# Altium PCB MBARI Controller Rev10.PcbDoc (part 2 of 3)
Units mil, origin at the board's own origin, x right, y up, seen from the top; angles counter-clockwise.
Board outline 10420.2 x 10420.2 mil, 2 copper layers (Top Layer, Bottom Layer); 286 components, 204 nets, 1058 pads, 249 vias.
Unrouted connection lines stored in the file: 1.

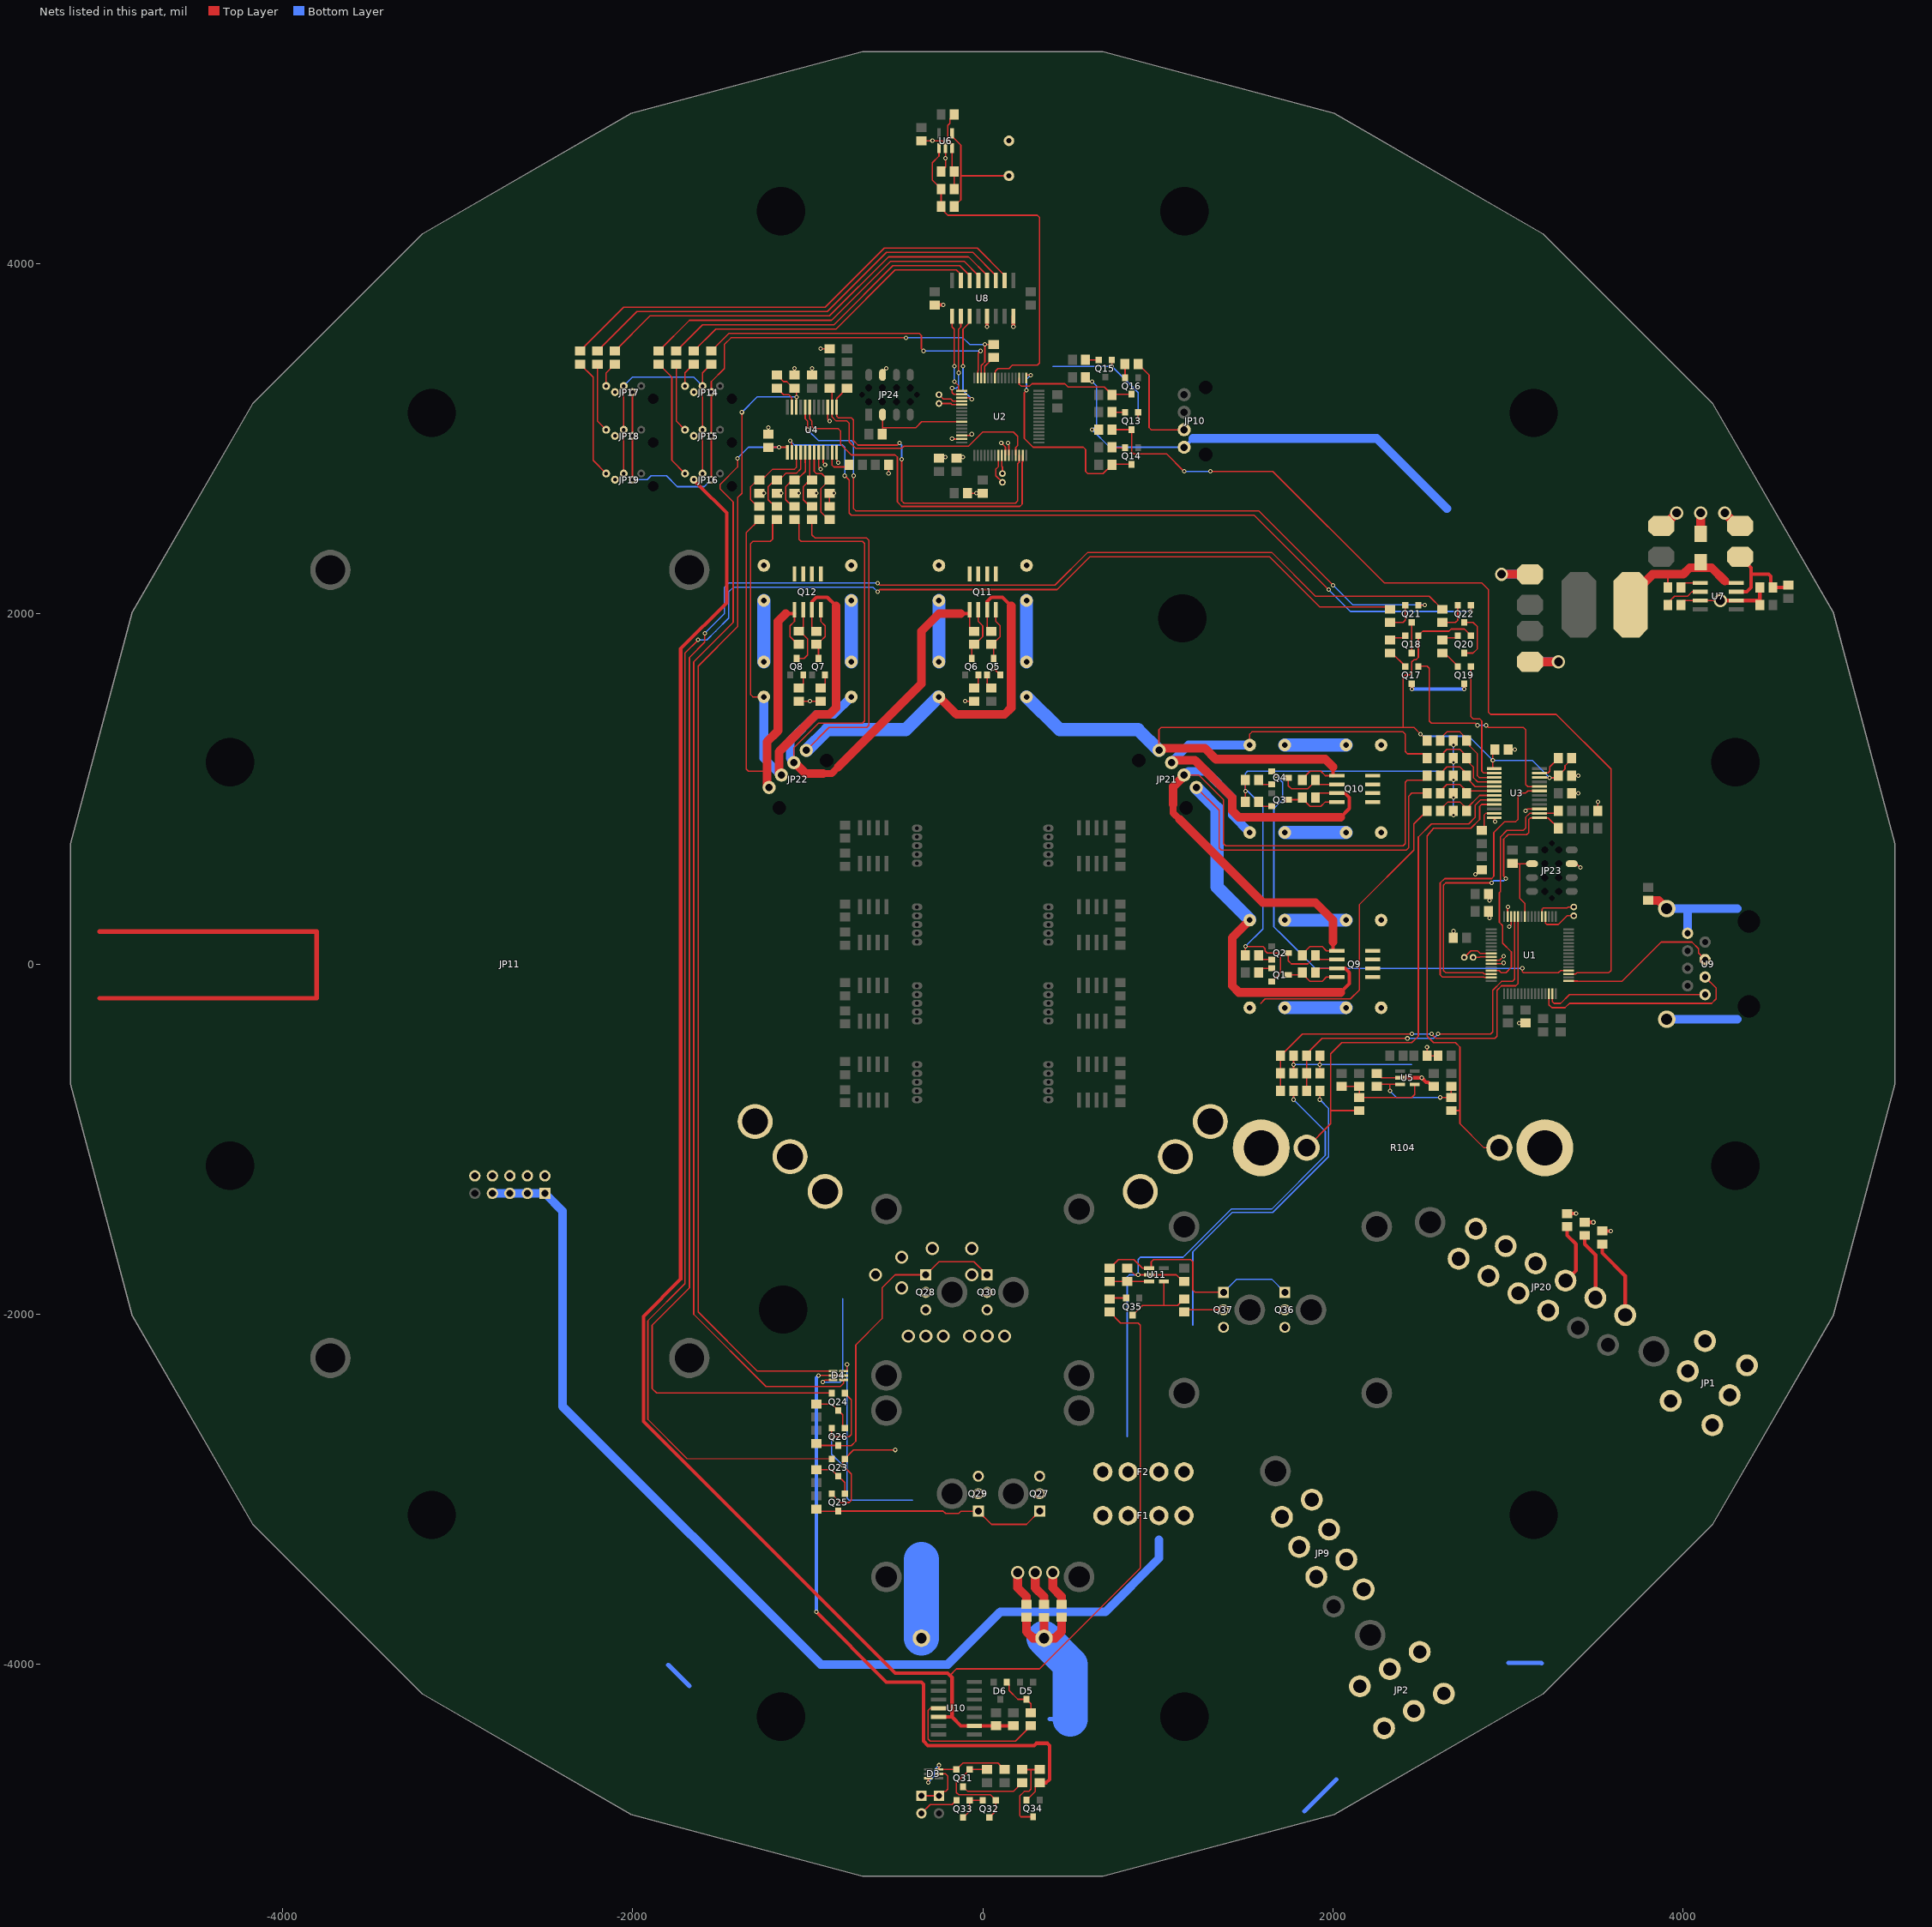
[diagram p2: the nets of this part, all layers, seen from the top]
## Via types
v1: diameter 25, hole 15, Top Layer to Bottom Layer, 204 vias
v2: diameter 40, hole 22, Top Layer to Bottom Layer, 24 vias
v3: diameter 75, hole 50, Top Layer to Bottom Layer, 21 vias

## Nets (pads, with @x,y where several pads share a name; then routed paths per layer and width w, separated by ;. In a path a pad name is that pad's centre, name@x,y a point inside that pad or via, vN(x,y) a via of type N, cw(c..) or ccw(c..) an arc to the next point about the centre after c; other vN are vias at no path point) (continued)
AGNDU: C2.1 C4.1 C6.2 C8.2 C12.2 C14.1 C16.1 C20.1 C21.2 C22.1 C23.2 C24.1 C30.1 C31.1 C32.1 C33.1 C34.1 C35.1 C39.1 C41.2 JP14.4 JP15.4 JP16.4 JP17.4 JP18.4 JP19.4 JP21.4 JP24.7 Q5.2 Q10.1 Q13.1 Q15.1 Q18.1 Q20.1 R12.1 R30.2 R56.1 R62.2 R71.1 R75.2 R76.1 R80.1 R84.1 R103.2 RH1.2 U2.10 U2.11 U2.62 U2.63 U3.1 U3.22 U4.8 U4.9 U4.12 U4.15 U6.2 U8.5 U8.8 U10.5 U10.9 | length 20293.5
  Top Layer w8: C30.1@-1275,2687.5 v1(-1250,2687.5) ; C24.1@-1225,3024.8 v1(-1225,3062.5) ; C31.1@-1175,2687.6 C31.1@-1150.1,2687.6 ; C32.1@-1075,2687.6 C32.1@-1050.1,2687.6 ; C22.1@-1075,3362.4 v1(-1075,3400) ; R84.1@-1050,1500.2 R80.1@-925,1500.2 ; C33.1@-975,2687.6 C33.1@-950.1,2687.6 ; C4.1@-975,3362.4 v1(-975,3400) ; U4.8@-936.61,2921.06 -936.61,2836.61 v1(-925,2825) ; v1(-925,3512.5) -924.9,3512.4 C8.2@-875,3512.4 ; U4.9@-911.02,2921.06 -911.02,2861.02 v1(-900,2850) ; U4.15@-885.43,3178.94 -885.43,3110.43 v1(-875,3100) ; R71.1@-875,2612.4 C34.1@-875,2687.6 v1(-850.1,2687.6) ; U4.12@-834.25,2921.06 -834.25,2871.75 v1(-825,2862.5) ; JP24.7@-571.85,3363.19 -571.85,3378.15 v1(-550,3400) ; v1(-537.5,2800) C20.1@-537.5,2850 ; C35.1@-350,4700 -231.25,4700 U6.2@-212.5,4681.25 ; R56.1@-237.5,4525 -212.5,4550 U6.2@-212.5,4657.68 ; C6.2@-231.25,2893.75 v1(-212.5,2893.75) ; v1@-225.2,3762.7 v1(-225,3762.5) ; -187.5,-4062.5 -150,-4025 325,-4025 900,-3450 900,-2062.5 887.5,-2050 787.5,-2050 725,-1987.5 R62.2@725,-1987.4 ; v1(-175,3000) -172.05,2997.05 U2.63@-120.47,2997.05 ; C2.1@-131.25,2893.75 v1(-112.5,2893.75) ; U2.62@-120.47,3016.73 -70.77,3016.73 v1(-62.5,3025) ; v1(-100,1500) R76.1@-50,1500 ; C12.2@-87.6,2687.5 v1@-37.5,2687.5 ; v1(-37.4,2687.6) C14.1@0,2687.6 ; v1(62.5,1687.5) 99.8,1650.2 Q5.2@99.8,1650 ; v1(106.25,2975) 129.53,2951.72 U2.10@129.53,2904.53 ; v1(143.75,2975) 149.21,2961.71 U2.11@149.21,2904.53 ; v1@737.4,3412.6 Q15.1@737.4,3449.21 ; v1@887.4,3112.6 Q13.1@887.4,3149.21 ; JP21.4@1001.01,1219.76 JP21.4@1007.63,1219.76 JP21.4@1007.63,1220.13 ; JP21.4@1006.25,1221.14 1006.25,1337.5 1018.75,1350 2462.6,1350 v1(2500,1312.5) R12.1@2537.6,1275 R12.1@2537.5,1275 ; R30.2@1825.2,1050 1825.2,1056.45 1868.75,1100 1931.25,1100 1956.25,1075 Q10.1@2022.64,1075 ; 2400,1350 2400,1637.5 2412.5,1650 2437.5,1650 2450,1662.5 2450,1725 2462.7,1737.7 2475,1737.7 2487.4,1750.1 2487.4,1874.9 2512.5,1900 2662.5,1900 2675,1912.5 2750,1912.5 Q20.1@2787.4,1875.1 ; Q20.1@2787.4,1873.43 Q20.1@2787.4,1887.6 ; U3.1@2921.06,1115.75 2921.06,1116.44 2912.5,1125 2912.5,1212.5 C23.2@2925,1225 ; U3.22@3178.94,1064.57 3222.93,1064.57 3225,1062.5 3275.2,1062.5 3325,1112.3 3325,1131.25 3362.5,1168.75 R103.2@3362.5,1175
  Top Layer w20: JP16.4@-1650,2765 -1625,2737.5 -1462.5,2575 -1462.5,2062.5 -1725,1800 -1725,-1800 -1937.5,-2012.5 -1937.5,-2612.5 -500,-4050 -200,-4050 -175,-4075 -175,-4300 ; C16.1@-275,3762.7 v1@-225.2,3762.7 ; U10.5@-252.36,-4300 -175,-4300 ; v1(25,3637.5) U8.5@25,3700 ; C41.2@174.8,-4350 C39.1@75,-4350 -125,-4350 -175,-4300 ; v1(175,3637.5) U8.8@175,3697.64 ; Q10.1@2000,1075 2000,1125
  Top Layer w50: JP21.4@1007.63,1219.76 1019.12,1231.25 1050,1231.25 1268.75,1231.25 1331.25,1168.75 1956.25,1168.75 2000,1125
  Bottom Layer w8: 400.76,3412.5 418.75,3412.5 v1@737.4,3412.6 ; v1(737.5,3412.5) 887.5,3262.5 v1(887.5,3112.5) ; v1(2500,1312.5) 2512.5,1300 2775,1300 v1(2912.5,1162.5) 3137.5,1162.5 v1(3237.5,1062.5)
  Bottom Layer w50: JP21.4@1005.24,1219.76 JP21.4@1007.63,1219.76
  Bottom Layer w75: R75.2@250,1525 440.23,1337.5 887.5,1337.5 JP21.4@1005.24,1219.76
  other v1: -987.5,1500.2 -1150,2687.5 -1050,2687.5 -950,2687.5 -212.5,4600 -287.5,4700
BAT+: D4.3 JP6.1 JP7.1 JP8.1 Q28.2 Q30.2 | length 642.1
  Top Layer w8: v1(-912.5,-2387.5) -900.59,-2375.59 D4.3@-855.51,-2375.59
  Bottom Layer w8: v1(-912.5,-2387.5) -812.5,-2387.5 -800,-2375 -800,-1912.5
  other v3: -462.5,-1850 -612.5,-1775 -62.5,-1775 -462.5,-1675 -287.5,-1625 -62.5,-1625
BAT-: JP3.1 JP4.1 JP5.1 R16.1 R20.2 R104.4 | length 1779.2
  Top Layer w8: 1587.5,-225 1612.5,-200 2100,-200 2150,-150 2150,162.5 2150,337.5 2462.5,650 2462.5,800 2537.5,875 R16.1@2537.6,875
CS0: JP14.5 R45.2 | length 148.5
  Top Layer w8: JP14.5@-1702.73,3300.73 JP14.5@-1700,3300 -1700,3375 R45.2@-1650,3425
CS1: JP15.5 R46.2 | length 395.7
  Top Layer w8: R46.2@-1750,3425 -1750,3100 JP15.5@-1700,3050
CS2: JP16.5 R47.2 | length 687.1
  Top Layer w8: R47.2@-1850,3425 -1775,3350 -1775,2875 JP16.5@-1700,2800
CS3: JP17.5 R48.2 | length 148.8
  Top Layer w8: JP17.5@-2152.74,3300.73 JP17.5@-2150,3300 ; JP17.5@-2150.22,3300.06 JP17.5@-2150,3300 ; R48.2@-2100,3425 -2150,3375 JP17.5@-2150,3300
CS4: JP18.5 R49.2 | length 397.6
  Top Layer w8: R49.2@-2200,3425 -2200,3100 JP18.5@-2150,3050 JP18.5@-2151.62,3049.06
CS5: JP19.5 R50.2 | length 687.1
  Top Layer w8: R50.2@-2300,3425 -2225,3350 -2225,2875 JP19.5@-2150,2800
CTS: U1.31 U9.8 | length 941.7
  Top Layer w8: U1.31@3252.95,-170.47 3252.95,-215.45 3262.5,-225 3300,-225 3350,-175 U9.8@4125,-175
F_RH: R54.2 R57.2 U2.42 U6.1 | length 2107.9
  Top Layer w8: U6.1@-249.9,4657.68 -249.9,4612.6 -287.5,4575 -287.5,4475.2 -237.5,4425.2 -237.5,4425 R54.2@-237.5,4325 ; R54.2@-237.4,4325 -237.4,4312.4 -200,4275 312.5,4275 325,4262.5 325,3431.25 312.5,3418.75 168.75,3418.75 150,3400 87.5,3400 72.25,3384.75 72.25,3378.5 70.47,3376.72 U2.42@70.47,3345.47
FUSE_EXT: C17.2 R58.1 R59.2 U1.61 | length 2072.8
  Top Layer w8: R58.1@1850,-725 R59.2@1850,-625 ; R59.2@1850.2,-624.8 1850.2,-512.5 1937.7,-425 v1(2425,-425) ; v1(2600,-400) 2675,-400 2700,-400 2900,-400 2912.5,-387.5 2912.5,-150 2962.5,-100 3025,-100 3037.5,-87.5 3037.5,168.75 3037.5,181.25 3037.5,218.75 3036.42,232.33 U1.61@3036.42,270.47
  Bottom Layer w8: v1(2425,-425) 2575,-425 v1(2600,-400)
FUSE_INT: C18.2 R60.1 R61.2 U1.60 | length 2284.4
  Top Layer w8: R60.1@1700.2,-725 C18.2@1700.2,-525 1825.2,-400 v1(2450,-400) ; v1(2562.5,-400) 2587.5,-425 2925,-425 2937.5,-412.5 2937.5,-150 2962.5,-125 3043.75,-125 3056.25,-112.5 3056.25,231.25 3056.1,231.4 U1.60@3056.1,270.47
  Bottom Layer w8: v1(2450,-400) v1(2562.5,-400)
NetC10_1: C10.1 R1.1@2150,-762.6 R3.2 U5.4 | length 545
  Top Layer w8: C10.1@2050,-699.9 R3.2@2150,-699.9 R1.1@2150,-762.6 2449.9,-762.6 2467.32,-745.18 U5.4@2467.32,-687.4
NetC22_2: C22.2 D4.1 R66.2 U4.22 | length 6743.1
  Top Layer w8: v1(-1375,3150) -1375,2687.5 -1400,2662.5 -1400,1925 -1625,1700 -1625,-1987.5 -1287.5,-2325 D4.1@-855.51,-2324.41 ; R66.2@-1175,3362.5 -1137.5,3325 -1118.75,3325 -1081.35,3287.6 C22.2@-1075,3287.6 -1064.57,3277.17 U4.22@-1064.57,3178.94
  Bottom Layer w8: v1(-1375,3150) -1287.5,3237.5 v1(-1062.5,3237.5)
NetC24_2: C24.2 D4.4 U4.1 | length 6505.6
  Top Layer w8: v1(-1400,2887.5) -1400,2837.5 -1500,2737.5 -1500,2712.5 -1425,2637.5 -1425,1950 -1650,1725 -1650,-2000 -1237.5,-2412.5 -812.5,-2412.5 -794.49,-2394.49 D4.4@-794.49,-2375.59 ; C24.2@-1225,2950 -1119,2950 -1115.75,2946.75 U4.1@-1115.75,2921.06
  Bottom Layer w8: v1(-1400,2887.5) -1337.5,2950 v1(-1162.5,2950)
NetC25_2: C25.2 R12.2 U3.3 | length 507.4
  Top Layer w8: R12.2@2612.4,1275 2612.4,1287.4 2650,1325 2725,1325 2762.4,1287.6 C25.2@2762.4,1275 2781.25,1256.25 2781.25,1243.75 2825,1200 2825,1075 2835.43,1064.57 U3.3@2896.06,1064.57
NetC26_2: C26.2 R13.2 U3.4 | length 399.2
  Top Layer w8: R13.2@2612.4,1187.4 2650,1225 2725,1225 2762.4,1187.6 C26.2@2762.4,1175 ; C26.2@2781.25,1156.15 2781.25,1143.75 2802.95,1122.05 2802.95,1062.5 2826.48,1038.98 U3.4@2896.06,1038.98
NetC27_2: C27.2 R14.2 U3.5 | length 360.5
  Top Layer w8: R14.2@2612.4,1087.4 2650,1125 2725,1125 2762.4,1087.6 C27.2@2762.4,1075 2781.25,1056.15 2781.25,1043.75 2812.5,1012.5 2825,1012.5 U3.5@2896.06,1013.39
NetC28_2: C28.2 R15.2 U3.6 | length 357.4
  Top Layer w8: R15.2@2612.4,975 2612.4,987.4 2650,1025 2725,1025 2762.4,987.6 C28.2@2762.4,975 2765.69,975 2778.19,987.5 2818.75,987.5 U3.6@2908.56,987.79
NetC29_2: C29.2 R16.2 U3.7 | length 390.9
  Top Layer w8: R16.2@2612.4,875 2618.65,887.4 2656.25,925 2725,925 2762.4,887.6 C29.2@2762.4,875 ; C29.2@2762.4,887.4 2837.2,962.2 U3.7@2921.06,962.2
NetC30_2: C30.2 R67.2 U4.3 | length 507.3
  Top Layer w8: R67.2@-1275,2612.4 -1287.4,2612.4 -1325,2650 -1325,2725 -1287.6,2762.4 C30.2@-1275,2762.4 C30.2@-1256.25,2781.15 ; C30.2@-1256.25,2781.25 -1243.75,2781.25 -1200,2825 -1075,2825 -1064.57,2835.43 U4.3@-1064.57,2896.06
NetC31_2: C31.2 R68.2 U4.4 | length 386.6
  Top Layer w8: C31.2@-1187.6,2762.4 -1225,2725 -1225,2650 R68.2@-1187.4,2612.4 ; C31.2@-1156.15,2781.25 -1143.75,2781.25 -1122.05,2802.95 -1062.5,2802.95 -1038.98,2826.48 U4.4@-1038.98,2896.06
NetC32_2: C32.2 R69.2 U4.5 | length 321.2
  Top Layer w8: C32.2@-1087.6,2762.4 -1125,2725 -1125,2650 R69.2@-1087.4,2612.4 ; C32.2@-1056.15,2781.25 -1043.75,2781.25 -1012.5,2812.5 -1012.5,2825 U4.5@-1013.39,2896.06
NetC33_2: C33.2 R70.2 U4.6 | length 311.4
  Top Layer w8: U4.6@-987.79,2908.56 -987.5,2818.75 C33.2@-987.5,2778.19 ; C33.2@-987.6,2762.4 -1025,2725 -1025,2650 R70.2@-987.4,2612.4
NetC34_2: C34.2 R71.2 U4.7 | length 486.8
  Top Layer w8: U4.7@-962.21,2921.06 -962.5,2812.5 -950,2800 -918.75,2800 -881.15,2762.4 C34.2@-875,2762.4 -925,2712.4 -925,2581.25 -881.35,2537.6 R71.2@-875,2537.6
NetC40_1: C40.1 D5.3 D6.1 | length 262
  Top Layer w8: D6.1@138.29,-4100.79 D6.1@137.4,-4100.79 150,-4113.38 150,-4148.42 200.79,-4199.21 D5.3@250,-4199.21 ; D5.3@249.21,-4200 D5.3@250,-4199.21 ; C40.1@275,-4275 275,-4224.21 D5.3@250,-4199.21
NetC40_2: C40.2 U10.4 | length 856.8
  Top Layer w8: U10.4@-252.36,-4250 -300,-4250 -312.5,-4262.5 -312.5,-4425 -300,-4437.5 187.3,-4437.5 C40.2@275,-4349.8
NetC44_2: C44.2 C45.1 L3.2 U7.7 | length 556.9
  Top Layer w8: C44.2@4500,2162.4 C44.2@4512.4,2150
  Top Layer w20: U7.7@4302.36,2125 4362.5,2125 4387.5,2150 4387.5,2225 ; C45.1@4325,2325 4387.5,2262.5 4387.5,2225 ; C44.2@4500,2162.4 4500,2212.5 4487.5,2225 4412.5,2225 4387.5,2225 ; C44.2@4512.4,2150 L3.2@4587.6,2150
NetC46_1: C46.1 U7.2 | length 223.5
  Top Layer w8: C46.1@3912.6,2050 3925,2062.4 3925,2075 3950,2100 4025,2100 4050,2125 U7.2@4097.64,2125
NetC47_1: C47.1 U7.1 | length 127.9
  Top Layer w8: C47.1@3987.4,2150 3987.4,2162.4 4000,2175 U7.1@4097.64,2175
NetC47_2: C47.2 D1.2 L4.1 U7.8 | length 831
  Top Layer w8: L4.1@3700,2050 L4.1@3700,2100 ; 3912.5,2225 3912.6,2224.9 C47.2@3912.6,2150
  Top Layer w20: 4237.5,2187.5 4250,2175 U7.8@4302.36,2175
  Top Layer w50: L4.1@3700,2100 3825,2225 4000,2225 4037.5,2262.5 4162.5,2262.5 4237.5,2187.5
NetC52_2: C52.2 JP20.10 | length 354.2
  Top Layer w20: JP20.10@3327.77,-1808.13 3387.5,-1750 3387.5,-1600 3337.5,-1550 C52.2@3337.5,-1499.9
NetC53_2: C53.2 JP20.11 | length 383.3
  Top Layer w20: C53.2@3437.5,-1549.9 3437.5,-1600 3500,-1662.5 3500,-1905.01 JP20.11@3498.38,-1906.63
NetC54_2: C54.2 JP20.12 | length 459.7
  Top Layer w20: C54.2@3537.5,-1599.9 3537.5,-1650 3668.75,-1781.25 3668.75,-2004.9 JP20.12@3668.98,-2005.13
NetD3_3: D3.3 D3.6 Q31.2 R94.1 | length 577.3
  Top Layer w8: v1(-311.02,-4673.52) D3.3@-311.02,-4650 ; D3.6@-250,-4600 v1(-250,-4575) ; D3.6@-248.82,-4600 Q31.2@-150,-4600 -112.5,-4562.5 87.5,-4562.5 R94.1@125,-4600.2
  Bottom Layer w8: v1(-311.02,-4673.52) -275,-4637.5 -275,-4600 v1(-250,-4575)
NetD3_5: D3.5 JP12.1 JP13.1 | length 295.7
  Top Layer w8: JP12.1@-350,-4750 JP13.1@-250,-4750 -225,-4725 -212.5,-4725 -200,-4712.5 -200,-4637.5 -212.5,-4625 D3.5@-250,-4624.41
NetD4_2: D4.2 D4.5 Q34.2 R97.2 | length 3734.8
  Top Layer w8: v1(-937.5,-2350) D4.5@-794.49,-2350 ; Q34.2@250.2,-4775 250.2,-4774.8 300,-4725 300,-4700 R97.2@325,-4675
  Top Layer w20: v1(-950,-3700) -550,-4100 -350,-4100 -337.5,-4112.5 -337.5,-4437.5 -312.5,-4462.5 293.75,-4462.5 306.25,-4450 368.75,-4450 381.25,-4462.5 381.25,-4656.25 362.5,-4675 R97.2@325,-4675
  Bottom Layer w20: v1(-950,-3700) -950,-2362.5 v1(-937.5,-2350)
NetJP21_1: JP21.1 Q9.3 R15.1 R18.2 R24.2 | length 4178.3
  Top Layer w8: JP21.1@1219.76,1007.63 1350,877.39 1350,662.5 1362.5,650 2418.75,650 2432.5,663.75 2432.5,957.5 2450,975 R15.1@2537.6,975 ; R18.2@1900,-50 1925,-25 2068.75,-25
  Top Layer w20: 2043.75,-162.5 2093.75,-112.5 2093.75,-50 2068.75,-25
  Top Layer w50: R24.2@1525,250 1425,150 1425,-125 1462.5,-162.5 2043.75,-162.5
  Bottom Layer w50: JP21.1@1219.76,1005.24 JP21.1@1219.76,1007.63
  Bottom Layer w75: JP21.1@1219.76,1005.24 1337.5,887.5 1337.5,440.23 R24.2@1525,252.73
NetJP21_2: JP21.2 Q9.1 R14.1 R22.2 R28.2 | length 4471.8
  Top Layer w8: JP21.2@1149.05,1078.34 1234.16,1078.34 1375,937.5 1375,687.5 1387.5,675 2400,675 2412.5,687.5 2412.5,1037.5 2425,1050 2512.5,1050 2537.5,1075 R14.1@2537.6,1075 ; R22.2@1825.2,50 1825.2,56.45 1868.75,100 1937.5,100 1962.5,75 Q9.1@2022.64,75
  Top Layer w20: Q9.1@2000,75 2000,125
  Top Layer w40: 1087.5,912.5 1087.5,862.5 1125,825
  Top Layer w50: 1087.5,912.5 1087.5,1012.5 JP21.2@1149.05,1074.05 ; 1125,825 1600,350 1900,350 2000,250 2000,125 ; JP21.2@1149.05,1078.34 JP21.2@1153.34,1078.34
  Bottom Layer w50: JP21.2@1153.34,1078.34 1175,1100 1275,1100 1425,950 1425,850 R28.2@1525,750
NetJP21_3: JP21.3 Q10.3 R13.1 R26.2 R32.2 | length 3155.4
  Top Layer w8: R32.2@1525,1250 1525,1312.5 1537.5,1325 2400,1325 2412.5,1312.5 2412.5,1212.5 2425,1200 2512.6,1200 R13.1@2537.6,1175 ; R26.2@1925,975 2068.75,975
  Top Layer w20: 2043.75,837.5 2093.75,887.5 2093.75,950 2068.75,975
  Top Layer w50: JP21.3@1078.34,1149.05 1087.5,1162.5 1212.5,1162.5 1425,950 1425,875 1462.5,837.5 2043.75,837.5
  Bottom Layer w50: JP21.3@1078.34,1149.05 1078.34,1153.34 1175,1250 R32.2@1525,1250
NetJP22_1: JP22.1 Q11.3 R70.1 R73.2 R79.2 | length 4178.4
  Top Layer w8: JP22.1@-1007.63,1219.76 -877.39,1350 -662.5,1350 -650,1362.5 -650,2418.75 -663.75,2432.5 -957.5,2432.5 -975,2450 R70.1@-975,2537.6 ; 25,2068.75 25,1924.8 R73.2@50,1899.8
  Top Layer w20: 25,2068.75 50,2093.75 112.5,2093.75 162.5,2043.75
  Top Layer w50: R79.2@-250,1525 -150,1425 125,1425 162.5,1462.5 162.5,2043.75
  Bottom Layer w50: JP22.1@-1007.63,1219.76 JP22.1@-1005.24,1219.76
  Bottom Layer w75: JP22.1@-1005.24,1219.76 -887.5,1337.5 -440.23,1337.5 R79.2@-252.73,1525
NetJP22_2: JP22.2 Q11.1 R69.1 R77.2 R83.2 | length 4372.6
  Top Layer w8: JP22.2@-1078.34,1149.05 -1078.34,1234.16 -937.5,1375 -687.5,1375 -675,1387.5 -675,2400 -687.5,2412.5 -1037.5,2412.5 -1050,2425 -1050,2512.5 R69.1@-1075,2537.5 ; Q11.1@-75,2022.64 -75,1924.8 R77.2@-50,1899.8
  Top Layer w20: -125,2000 Q11.1@-75,2000
  Top Layer w40: -912.5,1087.5 -862.5,1087.5 -825,1125
  Top Layer w50: JP22.2@-1074.05,1149.05 -1012.5,1087.5 -912.5,1087.5 ; -825,1125 -350,1600 -350,1900 -250,2000 -125,2000
  Bottom Layer w50: JP22.2@-1078.34,1149.05 -1078.34,1153.34 -1100,1175 -1100,1275 -950,1425 -850,1425 R83.2@-750,1525
NetJP22_3: JP22.3 Q12.3 R68.1 R81.2 R87.2 | length 3190.9
  Top Layer w8: R87.2@-1250,1525 -1312.5,1525 -1325,1537.5 -1325,2400 -1312.5,2412.5 -1212.5,2412.5 -1200,2425 -1200,2512.6 R68.1@-1175,2537.6 ; -975,2068.75 -975,1924.8 R81.2@-950,1899.8
  Top Layer w20: -975,2068.75 -950,2093.75 -887.5,2093.75 -837.5,2043.75
  Top Layer w50: JP22.3@-1153.34,1078.34 JP22.3@-1149.05,1078.34 -1162.5,1087.5 -1162.5,1212.5 -950,1425 -875,1425 -837.5,1462.5 -837.5,2043.75
  Bottom Layer w50: R87.2@-1250,1525 -1250,1175 JP22.3@-1153.34,1078.34
NetJP22_4: JP22.4 Q12.1 R67.1 R85.2 | length 2903.9
  Top Layer w8: R67.1@-1275,2537.6 -1350,2462.6 -1350,1112.5 -1337.5,1100 -1231.25,1100 ; Q12.1@-1075,2022.64 -1075,1956.25 -1100,1931.25 -1100,1868.75 -1056.45,1825.2 R85.2@-1050,1825.2
  Top Layer w20: -1125,2000 Q12.1@-1075,2000
  Top Layer w50: JP22.4@-1219.76,1007.63 -1231.25,1019.12 -1231.25,1050 -1231.25,1268.75 -1168.75,1331.25 -1168.75,1956.25 -1125,2000
  Bottom Layer w50: JP22.4@-1220.13,1007.63 JP22.4@-1219.76,1007.63
NetQ1_1: Q1.1 R17.2 | length 85.6
  Top Layer w8: R17.2@1574.8,-50 1599.8,-25 Q1.1@1650,-25
NetQ1_3: Q1.3 Q9.4 R18.1 | length 318.1
  Top Layer w8: Q1.3@1744.49,-62.4 1812.79,-62.4 R18.1@1825.2,-50 1825.2,-56.45 1868.75,-100 1937.5,-100 1962.5,-75 Q9.4@2022.64,-75
NetQ2_2: Q2.2 R21.2 | length 85.4
  Top Layer w8: R21.2@1575,50 1600,25 Q2.2@1650,25
NetQ2_3: Q2.3 Q9.2 R22.1 | length 364.7
  Top Layer w8: Q2.3@1744.49,62.4 1744.49,18.01 1762.5,0 1856.25,0 1900,43.75 R22.1@1900,50 1925,25 Q9.2@2022.64,25
NetQ3_2: Q3.2 R25.2 | length 50.2
  Top Layer w8: R25.2@1599.8,900.2 Q3.2@1650,900.2
NetQ3_3: Q3.3 Q10.4 R26.1 | length 300.6
  Top Layer w8: Q3.3@1744.49,937.6 R26.1@1812.79,937.6 ; R26.1@1825.2,950 1825.2,943.55 1868.75,900 1931.25,900 1956.25,925 Q10.4@2022.64,925
NetQ4_2: Q4.2 R29.2 | length 50.2
  Top Layer w8: R29.2@1599.8,1025.2 Q4.2@1650,1025.2
NetQ4_3: Q4.3 Q10.2 R30.1 | length 329.6
  Top Layer w8: Q4.3@1744.49,1062.6 1744.49,1018.01 1762.5,1000 1856.25,1000 1900,1043.75 R30.1@1900,1050 ; R30.1@1925,1025 Q10.2@2022.64,1025
NetQ5_1: Q5.1 R72.2 | length 85.6
  Top Layer w8: Q5.1@25,1650 25,1599.8 R72.2@50,1574.8
NetQ5_3: Q5.3 Q11.4 R73.1 | length 318
  Top Layer w8: Q5.3@62.4,1744.49 62.4,1812.6 R73.1@50,1825 56.25,1825 100,1868.75 100,1931.25 75,1956.25 Q11.4@75,2022.64
NetQ6_2: Q6.2 R76.2 | length 85.5
  Top Layer w8: R76.2@-50,1574.8 -25.2,1599.61 Q6.2@-25.2,1650
NetQ6_3: Q6.3 Q11.2 R77.1 | length 318.1
  Top Layer w8: Q6.3@-62.6,1744.49 -62.6,1812.4 R77.1@-50,1825 -43.75,1825 0,1868.75 0,1931.25 -25,1956.25 Q11.2@-25,2022.64
NetQ7_2: Q7.2 R80.2 | length 85.3
  Top Layer w8: R80.2@-925,1575 -900.2,1599.8 Q7.2@-900.2,1650
NetQ7_3: Q7.3 Q12.4 R81.1 | length 318
  Top Layer w8: Q7.3@-937.6,1744.49 -937.6,1812.6 R81.1@-950,1825 -931.25,1843.75 -925,1843.75 -900,1868.75 -900,1931.25 -925,1956.25 Q12.4@-925,2022.64
NetQ8_2: Q8.2 R84.2 | length 85.4
  Top Layer w8: R84.2@-1050,1575 -1025,1600 Q8.2@-1025,1650
NetQ8_3: Q8.3 Q12.2 R85.1 | length 363.9
  Top Layer w8: Q8.3@-1062.4,1744.49 -1019.49,1744.49 -1000,1763.98 -1000,1856.25 -1043.75,1900 R85.1@-1050,1900 -1025,1925 Q12.2@-1025,2022.64
NetQ9_5: Q9.5 Q9.6 R19.1
NetQ9_7: Q9.7 Q9.8 R23.1
NetQ10_5: Q10.5 Q10.6 R27.1
NetQ10_7: Q10.7 Q10.8 R31.1
NetQ11_5: Q11.5 Q11.6 R74.1
NetQ11_7: Q11.7 Q11.8 R78.1
NetQ12_5: Q12.5 Q12.6 R82.1
NetQ12_7: Q12.7 Q12.8 R86.1
NetQ13_2: Q13.2 R40.1 | length 74.4
  Top Layer w8: R40.1@738.19,3149.21 Q13.2@812.6,3149.21
NetQ14_2: Q14.2 R43.1 | length 72.4
  Top Layer w8: R43.1@740.16,2947.24 Q14.2@812.6,2947.24
NetQ15_2: Q15.2 R38.1 | length 75.2
  Top Layer w8: R38.1@587.4,3450 611.61,3449.21 Q15.2@662.6,3449.21
NetQ16_2: Q16.2 R41.1 | length 77.8
  Top Layer w8: Q16.2@812.6,3347.24 R41.1@812.6,3425
NetQ17_1: Q17.1 U3.20 | length 1335.8
  Top Layer w8: Q17.1@2487.4,1698.43 2488.98,1700 2537.5,1700 2550,1687.5 2550,1662.5 2550,1387.5 2562.5,1375 2812.5,1375 v1(2825,1362.5) ; v1(2875,1362.5) 2887.5,1350 3087.5,1350 3100,1337.5 3100,1025 3112.5,1012.5 U3.20@3178.94,1013.39
  Bottom Layer w8: v1(2825,1362.5) v1(2875,1362.5)
NetQ17_2: Q17.2 R35.1 | length 120.2
  Top Layer w8: R35.1@2325,1775 2337.5,1775 2412.6,1699.9 Q17.2@2412.6,1698.42
NetQ18_2: Q18.2 R35.2 | length 97.4
  Top Layer w8: R35.2@2325,1849.8 2337.7,1862.5 2400,1862.5 2410.93,1873.43 Q18.2@2412.6,1873.43
NetQ18_3: Q18.3 Q21.3 | length 175
  Top Layer w8: Q18.3@2450,1775 Q21.3@2450,1950
NetQ19_1: Q19.1 U3.2 | length 721.4
  Top Layer w8: Q19.1@2787.4,1698.43 2787.5,1412.5 2800,1400 2837.5,1400 2850,1387.5 2850,1100 2859.84,1090.16 U3.2@2921.06,1090.16
NetQ19_2: Q19.2 R33.1 | length 120.2
  Top Layer w8: R33.1@2625,1775 2637.5,1775 2712.6,1699.9 Q19.2@2712.6,1698.43
NetQ20_2: Q20.2 R33.2 | length 97.4
  Top Layer w8: R33.2@2625,1849.8 2637.7,1862.5 2700,1862.5 2710.93,1873.43 Q20.2@2712.6,1873.43
NetQ20_3: Q20.3 Q22.3 | length 295.7
  Top Layer w8: Q20.3@2750,1775 2800,1775 2825,1800 2825,1875 2825,1925 2800,1950 Q22.3@2750,1950
NetQ21_1: Q21.1 U4.20 | length 4331.6
  Top Layer w8: U4.20@-1013.39,3178.94 -1013.39,3113.39 -1000,3100 v1(-1000,3050) ; v1(-737.5,2787.5) -737.5,2600 -725,2587.5 1575,2587.5 v1(2000,2162.5) ; Q21.1@2487.4,2048.43 2523.43,2048.43 v1(2525,2050)
  Bottom Layer w8: v1(-1000,3050) -937.5,2987.5 -750,2987.5 -737.5,2975 v1(-737.5,2787.5) ; v1(2000,2162.5) 2112.5,2050 v1(2525,2050)
NetQ21_2: Q21.2 R36.1 | length 178.6
  Top Layer w8: R36.1@2325,1950 2400,1950 2412.6,1962.6 Q21.2@2412.6,2048.43
NetQ22_1: Q22.1 U4.2 | length 4602.7
  Top Layer w8: v1(-1100,2987.5) -1090.16,2977.66 U4.2@-1090.16,2921.06 ; v1(-787.5,2787.5) -762.5,2762.5 -762.5,2575 -750,2562.5 1550,2562.5 v1(1975,2137.5) ; v1(2787.4,2012.6) Q22.1@2787.4,2048.43
  Bottom Layer w8: v1(-1100,2987.5) -1075,2962.5 -800,2962.5 -787.5,2950 v1(-787.5,2787.5) ; v1(1975,2137.5) 2100,2012.5 2787.3,2012.5 v1(2787.4,2012.6)
NetQ22_2: Q22.2 R34.1 | length 178.6
  Top Layer w8: R34.1@2625,1950 2700,1950 2712.6,1962.6 Q22.2@2712.6,2048.43
NetQ23_1: Q23.1 Q24.1 Q25.2 Q26.2 Q27.3 Q28.3 Q29.3 Q30.3 | length 1317.6
  Top Layer w8: Q25.2@-862.4,-3025.79 -861.71,-3025.79 -812.5,-3075 -762.5,-3075 -750,-3062.5 -750,-2912.5 v1(-800,-2862.5) -800,-2837.5 Q23.1@-788.29,-2825.79 ; Q26.2@-861.71,-2650.79 Q26.2@-862.4,-2650.79 -862.4,-2699.9 v1(-862.5,-2700) -762.5,-2700 -750,-2687.5 -750,-2488.38 Q24.1@-787.6,-2450.79 ; Q23.1@-787.6,-2825.79 -787.6,-2825.1 -737.5,-2775 v1(-500,-2775)
  Bottom Layer w8: v1(-862.5,-2700) -862.5,-2800 v1(-800,-2862.5)
  other v3: -425,-2125 -325,-2125 -225,-2125 -75,-2125 25,-2125 125,-2125
NetQ23_2: Q23.2 R36.2 | length 10092.2
  Top Layer w8: v1(-1625,1850) -1700,1775 -1700,-1825 -1912.5,-2037.5 -1912.5,-2600 -1687.5,-2825 Q23.2@-862.4,-2825.79 ; v1(-600,2125) -587.5,2137.5 425,2137.5 612.5,2325 1637.5,2325 1925,2037.5 2312.5,2037.5 2325,2025 R36.2@2325,2024.8
  Bottom Layer w8: v1(-1625,1850) -1575,1850 -1525,1900 -1450,1975 -1450,2125 -1425,2150 -625,2150 v1(-600,2125)
NetQ23_3: Q23.3 Q25.1 R90.1 | length 257.2
  Top Layer w8: R90.1@-950,-2887.6 -862.4,-2887.6 -825.79,-2924.21 Q23.3@-825,-2924.21 -787.6,-2961.61 Q25.1@-787.6,-3025.79
NetQ24_2: Q24.2 R34.2 | length 10109.3
  Top Layer w8: v1(-1587.5,1887.5) -1587.5,1837.5 -1675,1750 -1675,-1850 -1887.5,-2062.5 -1887.5,-2425 -1862.5,-2450 Q24.2@-862.4,-2450.79 ; v1(-600,2175) -587.5,2162.5 412.5,2162.5 600,2350 1650,2350 1900,2100 2550,2100 2625,2025 R34.2@2625,2024.8
  Bottom Layer w8: v1(-1587.5,1887.5) -1475,2000 -1475,2150 -1450,2175 -625,2175 v1(-600,2175)
NetQ24_3: Q24.3 Q26.1 R91.1 | length 257.2
  Top Layer w8: R91.1@-950,-2512.6 -861.61,-2512.6 Q24.3@-825,-2549.21 -825,-2550 -800,-2575 -800,-2637.5 -787.6,-2649.9 Q26.1@-787.6,-2650.79
NetQ25_3: Q25.3 Q27.1 Q29.1 R88.1 | length 1359.6
  Top Layer w8: R88.1@-950,-3112.4 -950,-3125 Q25.3@-825.79,-3125 ; Q25.3@-825,-3124.21 -225.79,-3124.21 -212.5,-3137.5 -137.5,-3137.5 -125,-3125 Q29.1@-25,-3125 50,-3200 250,-3200 Q27.1@325,-3125
NetQ26_3: Q26.3 Q28.1 Q30.1 R89.1 | length 1877.4
  Top Layer w8: R89.1@-950,-2737.4 -950,-2748.43 -949.21,-2749.21 Q26.3@-825,-2749.21 -824.21,-2750 -750,-2750 -725,-2725 -725,-2175 -575,-2025 -575,-1850 -500,-1775 Q28.1@-325,-1775 -250,-1700 -50,-1700 Q30.1@25,-1775
NetQ31_1: Q31.1 Q32.1 Q32.3 R95.1 | length 619.3
  Top Layer w8: R95.1@24.8,-4600 Q31.1@-75.2,-4600 -75.2,-4600.2 -150,-4675 -150,-4731.25 -137.5,-4743.75 43.75,-4743.75 Q32.1@75,-4775 75,-4836.02 Q32.3@37.6,-4873.43
NetQ31_3: Q31.3 R96.1 | length 369.3
  Top Layer w8: Q31.3@-112.6,-4698.42 -86.02,-4725 175,-4725 R96.1@225,-4675
NetQ32_2: Q32.2 Q33.1 Q33.3 | length 190
  Top Layer w8: Q33.3@-112.4,-4873.43 -110.93,-4873.43 -75,-4837.5 Q33.1@-75,-4775 Q32.2@0.2,-4775
NetQ34_3: Q34.3 R96.2 R97.1 | length 482.9
  Top Layer w8: R96.2@225,-4600.2 R97.1@325,-4600.2 ; 275,-4600.2 275,-4712.5 262.5,-4725 237.5,-4725 211.02,-4751.48 211.02,-4862.5 218.01,-4869.49 Q34.3@287.6,-4869.49
NetQ35_2: Q35.2 R62.1 | length 96.2
  Top Layer w8: R62.1@725,-1912.6 730.56,-1907.04 Q35.2@818.85,-1907.04
NetQ35_3: Q35.3 R93.2 U11.4 | length 466.4
  Top Layer w8: Q35.3@856.25,-2005.46 857.04,-2005.46 912.5,-1950 1112.6,-1950 R93.2@1150,-1912.6 ; 1034.65,-1946.6 U11.4@1034.65,-1812.4
NetQ36_1: Q36.1 Q37.1 R105.2 U11.1 | length 1319.2
  Top Layer w8: R105.2@725,-1737.5 775,-1687.5 862.5,-1687.5 912.6,-1737.6 U11.1@950,-1737.6 962.4,-1737.6 962.5,-1737.5 962.5,-1700 975,-1687.5 1187.5,-1687.5 1200,-1700 1200,-1862.5 1212.5,-1875 Q37.1@1375,-1875
  Bottom Layer w8: Q37.1@1375,-1875 1450,-1800 1650,-1800 Q36.1@1725,-1875
NetR1_2: R1.2@2150,-837.4 R104.3 U3.8 | length 2994.8
  Top Layer w8: R104.3@1850,-1050 1987.5,-912.5 1987.5,-512.5 2050,-450 2450,-450 2471.88,-428.12 ; 1987.5,-837.5 R1.2@2150,-837.4 ; 2473.69,-426.31 2487.5,-412.5 2487.5,725 2562.5,800 2775,800 2812.5,837.5 2812.5,906.25 2842.86,936.61 U3.8@2921.06,936.61
NetR2_1: R2.1 R4.2 R5.1 U5.3 | length 603.7
  Top Layer w8: R5.1@2250,-699.9 2262.5,-687.4 U5.3@2382.68,-687.4 ; v1(2325,-725) 2325,-687.4 ; v1(2612.5,-762.5) 2612.6,-762.6 R2.1@2675,-762.6 R4.2@2675,-699.9
  Bottom Layer w8: v1(2325,-725) 2362.5,-762.5 v1(2612.5,-762.5)
NetR2_2: R2.2 R104.2 U3.9 | length 2630.6
  Top Layer w8: R2.2@2675,-837.4 2725,-837.5 ; U3.9@2921.06,911.02 2848.52,911.02 2837.5,900 2837.5,825 2787.5,775 2575,775 2537.5,731.25 2537.5,-412.5 2575,-450 2700,-450 2725,-475 2725,-837.5 ; R104.2@2950,-1050 2862.5,-1050 2725,-912.5 2725,-837.5
NetR11_1: R11.1 U3.11 | length 155.4
  Top Layer w8: R11.1@2850,762.4 2862.5,774.9 2862.5,850 2872.34,859.84 U3.11@2921.06,859.84
NetR19_2: R19.2 R20.1 | length 350
  Bottom Layer w75: R20.1@1725,-250 R19.2@2075,-250
NetR23_2: R23.2 R24.1 | length 350
  Bottom Layer w75: R24.1@1725,250 R23.2@2075,250
NetR27_2: R27.2 R28.1 | length 350
  Bottom Layer w75: R28.1@1725,750 R27.2@2075,750
NetR31_2: R31.2 R32.1 | length 350
  Bottom Layer w75: R32.1@1725,1250 R31.2@2075,1250
NetR45_1: R45.1 U8.15 | length 1762.1
  Top Layer w8: R45.1@-1650,3499.8 -1524.8,3625 -837.5,3625 -500,3962.5 -150,3962.5 -125,3937.5 U8.15@-125,3902.36
NetR46_1: R46.1 U8.14 | length 1929.2
  Top Layer w8: R46.1@-1750,3499.8 -1599.8,3650 -850,3650 -512.5,3987.5 -131.25,3987.5 -75,3931.25 U8.14@-75,3902.36
NetR47_1: R47.1 U8.13 | length 2100
  Top Layer w8: R47.1@-1850,3499.8 -1850,3500 -1675,3675 -862.5,3675 -525,4012.5 -106.25,4012.5 -25,3931.25 U8.13@-25,3902.36
NetR48_1: R48.1 U8.12 | length 2420.6
  Top Layer w8: R48.1@-2100,3499.8 -1899.8,3700 -875,3700 -537.5,4037.5 -81.25,4037.5 25,3931.25 U8.12@25,3902.36
NetR49_1: R49.1 U8.11 | length 2591.3
  Top Layer w8: R49.1@-2200,3499.8 -1974.8,3725 -887.5,3725 -550,4062.5 -56.25,4062.5 75,3931.25 U8.11@75,3902.36
NetR50_1: R50.1 U8.10 | length 2762.2
  Top Layer w8: R50.1@-2300,3499.8 -2300,3500 -2050,3750 -900,3750 -562.5,4087.5 -31.25,4087.5 125,3931.25 U8.10@125,3902.36
NetR52_1: R52.1 U2.47 | length 1821.1
  Top Layer w8: R52.1@-1550,3499.8 -1449.8,3600 -362.5,3600 -350,3587.5 -350,3512.5 v1(-337.5,3500) ; U2.47@-27.95,3345.47 -27.95,3384.55 ; -25,3387.5 -25,3487.5 v1(-12.5,3500)
  Bottom Layer w8: v1(-337.5,3500) v1(-12.5,3500)
NetR53_1: R53.1 U2.45 | length 138.3
  Top Layer w8: U2.45@11.42,3345.47 11.42,3411.52 43.75,3443.85 R53.1@62.5,3462.6
NetR54_1: R54.1 RH1.1 U6.4 | length 728.7
  Top Layer w8: U6.4@-175.1,4742.32 -175.1,4725.1 -125,4675 -125,4500 ; R54.1@-162.7,4325 -125,4362.7 -125,4500 ; RH1.1@150,4500 -125,4500
NetR55_1: R55.1 R56.2 R57.1 U6.3 | length 456
  Top Layer w8: R55.1@-162.6,4850 -187.5,4825.1 -187.5,4800 -200,4787.5 -200,4706.25 -175.1,4681.35 U6.3@-175.1,4657.68 -175.1,4537.6 -162.5,4525 R57.1@-162.5,4425
NetR65_1: R65.1 U4.11 | length 180.4
  Top Layer w8: U4.11@-859.84,2921.06 -859.84,2847.34 -850,2837.5 -774.9,2837.5 -774.9,2837.6 R65.1@-762.5,2850
NetR66_1: R66.1 U4.23 | length 162.1
  Top Layer w8: R66.1@-1175,3287.7 -1137.31,3250.01 -1106.26,3250.01 -1090.16,3233.91 U4.23@-1090.16,3178.94
NetR74_2: R74.2 R75.1 | length 350
  Bottom Layer w75: R75.1@250,1725 R74.2@250,2075
NetR78_2: R78.2 R79.1 | length 350
  Bottom Layer w75: R79.1@-250,1725 R78.2@-250,2075
NetR82_2: R82.2 R83.1 | length 350
  Bottom Layer w75: R83.1@-750,1725 R82.2@-750,2075
NetR86_2: R86.2 R87.1 | length 350
  Bottom Layer w75: R87.1@-1250,1725 R86.2@-1250,2075
NetR92_2: R92.2 R105.1 U11.3 | length 224.8
  Top Layer w8: R105.1@725.2,-1812.5 R92.2@825,-1812.5 825.1,-1812.4 U11.3@950,-1812.4
NetR103_1: R103.1 U3.23 | length 158.4
  Top Layer w8: U3.23@3178.94,1090.16 3227.66,1090.16 3237.5,1100 3237.5,1124.8 R103.1@3287.7,1175
NetU1_8: U1.8@2904.53,59.84 Y1.2 | length 176.3
  Top Layer w8: Y1.2@2750,37.5 2787.5,75 2825,75 2840.16,59.84 U1.8@2904.53,59.84
NetU1_9: U1.9 Y1.1 | length 105.6
  Top Layer w8: Y1.1@2800,37.5 2837.5,37.5 2840.16,40.16 U1.9@2904.53,40.16
NetU1_52: U1.52 Y3.1 | length 223.3
  Top Layer w8: U1.52@3213.58,270.47 3213.58,232.33 3220.91,225 3287.5,225 3337.5,275 Y3.1@3375,275
NetU1_53: U1.53 Y3.2 | length 228.4
  Top Layer w8: U1.53@3193.9,270.47 3193.9,312.65 3200,318.75 3337.5,318.75 3343.75,325 Y3.2@3375,325
NetU2_8: U2.8 Y2.2 | length 352.7
  Top Layer w8: 75,2787.5 Y2.2@112.5,2750 75,2787.5 ; 75,2787.5 75,2825 ; 75,2787.5 75,2825 ; 75,2825 90.16,2840.16 ; 75,2825 90.16,2840.16 ; 90.16,2840.16 U2.8@90.16,2904.53 90.16,2840.16
NetU2_9: U2.9 Y2.1 | length 211.3
  Top Layer w8: 109.84,2840.16 112.5,2837.5 ; 109.84,2840.16 U2.9@109.84,2904.53 109.84,2840.16 ; 109.84,2840.16 112.5,2837.5 ; 112.5,2837.5 Y2.1@112.5,2800 112.5,2837.5
NetU2_49: U2.49 U8.1 | length 459.9
  Top Layer w8: U8.1@-175,3697.64 -175,3662.5 -175,3637.5 -162.5,3625 -162.5,3606.25 v1(-162.5,3412.5) ; v1(-162.5,3325) -137.5,3300 U2.49@-137.5,3275 ; U2.49@-141.39,3272.64 U2.49@-137.5,3275 ; U2.49@-120.47,3272.64 U2.49@-137.5,3275
  Bottom Layer w8: v1(-162.5,3325) v1(-162.5,3412.5)
NetU2_50: U2.50 U8.2 | length 529
  Top Layer w8: v1(-175,3287.5) -175,3262.5 -165.45,3252.95 U2.50@-120.47,3252.95 ; v1(-137.5,3375) -137.5,3600 -137.5,3625 -125,3637.5 -125,3662.5 U8.2@-125,3697.64
  Bottom Layer w8: v1(-175,3287.5) -150,3287.5 -137.5,3300 v1(-137.5,3375)
NetU2_51: U2.51 U8.3 | length 569.8
  Top Layer w8: U2.51@-120.47,3233.27 -72.98,3233.27 v1(-62.5,3225) ; v1(-112.5,3412.5) -112.5,3587.5 -112.64,3624.86 -75,3662.5 U8.3@-75,3697.64
  Bottom Layer w8: v1(-112.5,3412.5) -112.5,3275 v1(-62.5,3225)
NetU2_52: U2.52 Y4.1 | length 144.6
  Top Layer w8: Y4.1@-250,3250 -225,3225 -181.25,3225 -169.83,3213.58 U2.52@-120.47,3213.58
NetU2_53: U2.53 Y4.2 | length 132
  Top Layer w8: Y4.2@-250,3200 -181.25,3200 -174.85,3193.9 U2.53@-120.47,3193.9
PWR+: F1.1 F2.1 JP2.1 JP9.1 JP9.2 JP9.3 JP11.1 JP11.3 JP11.5 JP11.7 Q36.3 Q37.3 R58.2 | length 7745.7
  Top Layer w8: R58.2@1924.8,-725 v1(1925,-775)
  Bottom Layer w8: 1200,-2062.5 1200,-1643.75 1425,-1418.75 1656.25,-1418.75 1975,-1100 1975,-825 v1(1925,-775)
  Bottom Layer w50: JP11.7@-2800,-1310 JP11.5@-2700,-1310 JP11.3@-2600,-1310 JP11.1@-2500,-1310 -2400,-1410 -2400,-2525 -925,-4000 -200,-4000 100,-3700 700,-3700 1006.25,-3393.75 1006.25,-3287.5
PWR-: C1.1@2887.4,300 C3.1 C5.2 C7.2 C9.1 C11.2 C13.2 C15.1 C17.1 C18.1 C19.1 C21.1 C23.1 C25.1 C26.1 C27.1 C28.1 C29.1 C36.1 C37.1 C38.1 C43.1 C44.1 C45.2 C46.2 C48.1 C49.2 C50.2 C51.2 C52.1 C53.1 C54.1 D1.1 D2.1 JP1.1@3927.65,-2495.11 JP1.1@4026.15,-2324.5 JP1.1@4124.65,-2153.89 JP1.1@4166.67,-2633.11 JP1.1@4265.17,-2462.5 JP1.1@4363.67,-2291.89 JP9.5 JP9.6 JP9.7 JP9.8 JP10.4 JP11.2 JP11.4 JP11.6 JP11.8 JP11.10 JP12.2 JP20.3 JP20.4 JP20.8 JP20.9 JP23.7 Q1.2 Q17.3 Q19.3 Q33.2 R5.2 R21.1 R25.1 R29.1 R37.1 R39.1 R59.1 R61.1 R99.1 R104.1 U1.10 U1.11 U1.62 U1.63 U3.12 U3.15 U5.2 U7.3 U7.6 U9.1 U9.9 | length 16083.2
  Top Layer w8: JP12.2@-350,-4850 -300,-4800 -174.8,-4800 Q33.2@-149.8,-4775 ; R37.1@587.4,3325 v1(625,3325) ; v1(625,3050) R39.1@662.6,3050 ; R25.1@1500,925.2 R29.1@1500,1050.2 ; R21.1@1500.2,50 1500.2,99.8 v1(1500,100) 1600,100 1612.59,87.41 1612.59,74.91 1625,62.5 1687.5,62.5 1700,50 1700,-50 Q1.2@1650,-99.8 ; R61.1@1775,-625 C18.1@1775,-525 ; R59.1@1925,-624.8 C17.1@1925,-525 ; R5.2@2262.4,-612.7 R5.2@2250,-625.1 2275,-650 U5.2@2382.68,-650 U5.2@2387.5,-650 ; v1(2537.5,-475) 2537.4,-475.1 C11.2@2537.4,-525 C13.2@2600.1,-525 ; C9.1@2568.65,-699.9 C9.1@2575,-699.9 ; C15.1@2687.6,150 v1(2687.6,187.4) ; v1(2687.6,850.1) C29.1@2687.6,875 ; C28.1@2687.6,950.1 C28.1@2687.6,975 ; C27.1@2687.6,1050.1 C27.1@2687.6,1075 ; C26.1@2687.6,1150.1 C26.1@2687.6,1175 ; C25.1@2687.6,1250.1 C25.1@2687.6,1275 ; v1(2812.5,512.5) 2818.75,512.5 2843.85,537.6 C19.1@2850,537.6 ; C1.1@2887.4,300 2887.4,293.85 2893.75,281.25 v1(2893.75,262.5) ; C5.2@2887.4,400 2887.4,393.85 2893.75,381.25 v1(2893.75,362.5) ; U1.11@2904.53,0.79 2961.71,0.79 v1(2975,6.25) ; U1.10@2904.53,20.47 2951.72,20.47 v1(2975,43.75) ; U3.12@2921.06,834.25 2921.06,816.44 v1(2925,812.5) ; C23.1@2981.05,1225 v1(3037.5,1225) ; U1.63@2997.05,270.47 2997.05,322.05 v1(3000,325) ; v1(3006.25,212.5) 3016.73,222.98 U1.62@3016.73,270.47 ; v1(3062.5,-337.5) 3062.7,-337.3 R99.1@3100,-337.3 ; v1(3100,875) 3110.43,885.43 U3.15@3178.94,885.43 ; C3.1@3362.4,975 v1(3400,975) ; C21.1@3362.5,1075 v1(3400,1075) ; JP23.7@3363.19,571.85 3390.65,571.85 v1(3412.5,550) ; C7.2@3512.4,875 3512.4,924.9 v1(3512.5,925) ; C49.2@3875,2500 C49.2@3887.5,2500 ; C46.2@3987.4,2050 3987.4,2062.4 4000,2075 U7.3@4087.5,2075 ; U7.3@4100,2075 v3(4212.5,2075) ; C45.2@4312.5,2500 C45.2@4325,2500
  Top Layer w20: U5.2@2387.5,-650 v1(2506.25,-650) 2531.25,-675 2543.75,-675 C9.1@2568.65,-699.9 ; v1(2450,1568.75) Q17.3@2450,1600 ; v1(2750,1568.75) Q19.3@2750,1600 ; C52.1@3337.5,-1425.1 3387.4,-1425.1 v1(3387.5,-1425) ; C53.1@3437.5,-1475.1 3487.4,-1475.1 v1(3487.5,-1475) ; C54.1@3537.5,-1525.1 3587.4,-1525.1 v1(3587.5,-1525) ; v3(4212.5,2075) U7.6@4302.36,2075 C43.1@4437.6,2075 ; C43.1@4437.6,2050 C44.1@4437.6,2150
  Top Layer w25: -5043.75,-195 -3803.75,-195 -3803.75,185 -5043.75,185
  Top Layer w50: C38.1@250,-3731.05 250,-3812.5 287.5,-3850 D2.1@350,-3850 ; C37.1@350,-3731.25 D2.1@350,-3850 ; 450,-3812.5 412.5,-3850 D2.1@350,-3850 ; 450,-3800 C36.1@450,-3731.05 ; v3(2962.5,2225) C50.2@3125,2225 ; C51.2@3125,1725 v3(3287.5,1725) ; C48.1@3800,362.6 3859.4,362.6 U9.9@3906,316 ; C49.2@3887.5,2500 v3(3962.5,2575) ; D1.1@4100,2455.71 v3(4100,2575) ; v3(4237.5,2575) C45.2@4312.5,2500
  Bottom Layer w8: v1(625,3325) 650,3300 650,3075 v1(625,3050) 725,2950 JP10.4@1150,2950 ; v1(1500,100) 1600,200 1600,900 1512.5,987.5 v1(1500,987.5) 1500,1087.5 1512.5,1100 2600,1100 ; v1(1775,-575) 2450,-575 ; v1@2687.5,850.19 v1(2687.5,1250)
  Bottom Layer w20: JP10.4@1150,2950 1200,3000 ; v1(2450,1568.75) v1(2750,1568.75)
  Bottom Layer w25: -1796.74,-4002.91 -1794.65,-4002.91 -1674.55,-4123.01 ; 382.69,-4312.5 500,-4312.5 ; 1837.09,-4838 2018.61,-4656.47 ; 3001.8,-3991.75 3190.66,-3991.75 3191.56,-3992.65
  Bottom Layer w50: 1200,3000 1250,3000 2250,3000 2650,2600 ; v3(2962.5,2225) 3125,2225 ; 3125,1725 v3(3287.5,1725) ; U9.9@3906,-316 4309.75,-316 ; U9.9@3906,316 4309.75,316 ; U9.1@4025,175 4025,316
  Bottom Layer w200: D2.1@350,-3850 500,-4000 500,-4312.5
  other v1: 1925,-575 2687.5,950 2687.5,1050 2687.5,1150
PWRF+: C36.2 C37.2 C38.2 C42.1 D2.2 D4.6 F1.2 F2.2 Q27.2 Q29.2 R60.2 R92.1 U11.2 | length 5429.6
  Top Layer w8: D4.6@-794.49,-2324.41 -775.59,-2324.41 -775,-2323.82 v1(-775,-2287.5) ; R92.1@825,-1737.7 832.22,-1737.7 869.53,-1775 1105.47,-1775 C42.1@1142.78,-1812.3 ; C42.1@1149.8,-1812.3 C42.1@1150,-1812.3 ; v1(1775,-775) R60.2@1775,-725
  Top Layer w50: 200,-3562.7 v3(200,-3475) ; 200.2,-3562.7 250,-3612.5 C38.2@250,-3656.25 ; 300,-3562.7 v3(300,-3475) ; 300.2,-3562.89 350,-3612.7 C37.2@350,-3656.45 ; v3(400,-3475) 400,-3562.7 400.2,-3562.7 450,-3612.5 C36.2@450,-3656.25
  Bottom Layer w8: v1(-775,-2287.5) -775,-3050 -762.5,-3062.5 -400,-3062.5 ; 825,-2700 825,-1787.5 837.5,-1775 v1(887.5,-1775) 887.5,-1687.5 900,-1675 1143.75,-1675 1156.25,-1662.5 1418.75,-1400 1650,-1400 1956.25,-1093.75 1956.25,-956.25 v1(1775,-775)
  Bottom Layer w200: D2.2@-350,-3850 -350,-3400
PWRISO+: JP20.1 JP20.2 JP20.7 Q36.2 Q37.2 R93.1 | length 230.1
  Top Layer w8: R93.1@1150,-1987.4 1162.6,-1975 Q37.2@1375,-1975
RSTL: JP23.2 R7.2 U1.58 | length 424
  Top Layer w8: R7.2@3025,575.2 3028.35,571.85 JP23.2@3136.81,571.85 ; 3065.94,569.04 3065.94,375 3095.47,345.47 U1.58@3095.47,270.47
RSTU: JP24.2 R8.2 U2.58 | length 570.9
  Top Layer w8: R8.2@-571.85,3028.15 JP24.2@-571.85,3136.81 ; -571.85,3062.5 -381.25,3062.5 -348.28,3095.47 ; -345.47,3095.47 U2.58@-120.47,3095.47
RTS: U1.30 U9.6 | length 1195.6
  Top Layer w8: U1.30@3233.27,-170.47 3233.27,-233.27 3250,-250 3325,-250 3350,-225 4162.5,-225 4187.5,-200 4187.5,-137.5 U9.6@4125,-75
RX0L: U1.33 U9.4 | length 929.8
  Top Layer w8: U1.33@3345.47,-97.64 3397.64,-97.64 3400,-100 3650,-100 3875,125 4050,125 4087.5,87.5 4087.5,62.5 U9.4@4125,25
RX0U: Q14.3 R44.1 U2.33 | length 1207.6
  Top Layer w8: U2.33@247.64,3345.47 247.64,3360.14 250,3362.5 v1(275,3362.5) ; v1(250,3275) 237.5,3262.5 237.5,3000 287.5,2950 575,2950 587.5,2937.5 587.5,2812.5 600,2800 687.4,2800 R44.1@737.4,2850 ; R44.1@740.16,2852.76 Q14.3@850,2852.76
  Bottom Layer w8: v1(250,3275) 250,3337.5 v1(275,3362.5)
RX1L: Q13.3 R39.2 U1.35 | length 5536.5
  Top Layer w8: R39.2@738.19,3050.79 Q13.3@850,3050.79 850,2925 862.5,2912.5 1050,2912.5 v1(1150,2812.5) ; v1(1300,2812.5) 1656.25,2812.5 2293.75,2175 2850,2175 2887.5,2137.5 2887.5,1437.5 2900,1425 3275,1425 3587.5,1112.5 3587.5,-37.5 3575,-50 3393.75,-50 3385.48,-58.27 U1.35@3345.47,-58.27
  Bottom Layer w8: v1(1150,2812.5) v1(1300,2812.5)
RX1U: Q16.3 R42.1 U2.35 | length 713.3
  Top Layer w8: U2.35@208.27,3345.47 208.27,3310.48 218.75,3300 268.75,3300 281.25,3312.5 468.75,3312.5 487.5,3293.75 631.25,3293.75 643.75,3293.75 693.65,3293.75 R42.1@737.4,3250 740.16,3252.76 Q16.3@850,3252.76
RX3V: JP10.3 R41.2 | length 593.7
  Top Layer w8: R41.2@887.5,3425 R41.2@887.4,3425 950,3362.4 950,3062.5 962.5,3050 JP10.3@1150,3050
SC_T: JP14.3 JP15.3 JP16.3 JP17.3 JP18.3 JP19.3 R52.2 | length 1637.1
  Top Layer w8: JP19.3@-2050,2800 JP18.3@-2050,3050 JP17.3@-2050,3300 ; JP16.3@-1600,2800 JP15.3@-1600,3050 JP14.3@-1600,3300 -1600,3375 R52.2@-1550,3425
  Bottom Layer w8: JP17.3@-2050,3300 -2000,3350 -1650,3350 JP14.3@-1600,3300
SCLKL: R10.2 U1.14 U3.13 | length 1777
  Top Layer w8: U1.14@2904.53,-58.27 2864.52,-58.27 2856.25,-50 2643.75,-50 2631.25,-37.5 2631.25,450 2643.75,462.5 v1(2906.25,462.5) ; v1(2987.5,487.5) 2975,500 2975,712.5 3000,737.5 3106.25,737.5 3118.75,750 3118.75,825 3128,834.25 U3.13@3153,834.25 ; U3.13@3178.94,834.25 3228.44,834.25 R10.2@3287.7,775
  Bottom Layer w8: v1(2906.25,462.5) 2918.75,475 2975,475 v1(2987.5,487.5)
SCLKU: R64.2 U2.14 U4.13 | length 1960.3
  Top Layer w8: R64.2@-775,3287.7 -834.25,3228.44 -834.25,3128 -825,3118.75 -750,3118.75 -737.5,3106.25 -737.5,2987.5 -712.5,2962.5 -487.5,2962.5 v1(-475,2975) ; v1(-462.5,2881.25) -462.5,2643.75 -450,2631.25 187.5,2631.25 200,2643.75 200,2856.25 208.27,2864.52 U2.14@208.27,2904.53
  Bottom Layer w8: v1(-475,2975) -462.5,2962.5 -462.5,2893.75 v1(-462.5,2881.25)
SDATL: R9.2 U1.13 U3.14 | length 1336.7
  Top Layer w8: U1.13@2904.53,-38.58 2948.92,-38.58 2960.33,-50 2987.5,-50 3018.75,-18.75 3018.75,68.75 2968.75,118.75 2968.75,218.75 2950,237.5 2950,406.25 2956.25,412.5 2956.25,725 2993.75,762.5 3087.5,762.5 3100,775 3100,837.5 3122.34,859.84 3272.34,859.84 R9.2@3287.5,875
SDATU: R63.2 U2.13 U4.14 | length 1622.9
  Top Layer w8: R63.2@-875,3287.6 -859.84,3272.44 U4.14@-859.84,3178.94 ; R63.2@-859.84,3272.34 -859.84,3122.34 -837.5,3100 -775,3100 -762.5,3087.5 -762.5,2981.25 -725,2943.75 -462.5,2943.75 -450,2956.25 -81.25,2956.25 0,3037.5 175,3037.5 200,3012.5 200,2960.33 188.58,2948.92 U2.13@188.58,2904.53
SI/O_T: JP14.2 JP15.2 JP16.2 JP17.2 JP18.2 JP19.2 R53.2 U2.46 | length 3574.5
  Top Layer w8: JP19.2@-2000,2765 JP18.2@-2000,3015 JP17.2@-2000,3265 ; JP16.2@-1550,2765 JP15.2@-1550,3015 JP14.2@-1550,3265 -1550,3325 -1475,3400 -1475,3537.5 -1437.5,3575 -450,3575 v1(-437.5,3575) ; U2.46@-8.27,3345.47 -8.27,3416.73 12.5,3437.5 v1(12.5,3537.5) 56.15,3537.4 R53.2@62.5,3537.4
  Bottom Layer w8: JP19.2@-2000,2765 -1916.25,2765 -1893.75,2787.5 -1806.25,2787.5 -1743.75,2725 -1590,2725 JP16.2@-1550,2765 ; v1(-437.5,3575) -112.5,3575 -75,3537.5 v1(12.5,3537.5)
SLPL: U1.15 U3.19 | length 1834.4
  Top Layer w8: U1.15@2904.53,-77.95 2865.45,-77.95 2862.5,-75 2625,-75 2612.5,-62.5 2612.5,462.5 2637.5,487.5 2906.25,487.5 2918.75,500 2918.75,750 2981.25,812.5 3043.75,812.5 3056.25,825 3056.25,962.5 3068.75,975 3100,975 3112.5,987.5 3137.5,987.5 3137.79,987.79 U3.19@3178.94,987.79
SLPU: U2.15 U4.19 | length 1979.9
  Top Layer w8: U4.19@-987.8,3137.8 U4.19@-987.8,3178.94 ; U4.19@-987.5,3137.5 -987.5,3112.5 -975,3100 -975,3068.75 -962.5,3056.25 -825,3056.25 -812.5,3043.75 -812.5,2968.75 -750,2906.25 -500,2906.25 -487.5,2893.75 -487.5,2637.5 -462.5,2612.5 212.5,2612.5 225,2625 225,2862.5 ; 227.95,2865.45 U2.15@227.95,2904.53
TB0L: Q4.1 U1.36 | length 2740.2
  Top Layer w8: Q4.1@1650,1100 v1(1675,1075) ; v1(3081.25,-25) 3081.25,-43.75 3087.5,-50 3287.5,-50 3300,-37.5 U1.36@3343.75,-37.5
  Bottom Layer w8: v1(1675,1075) 1712.5,1037.5 1712.5,937.5 1662.5,887.5 1662.5,212.5 1712.5,162.5 1900,-25 v1(3081.25,-25)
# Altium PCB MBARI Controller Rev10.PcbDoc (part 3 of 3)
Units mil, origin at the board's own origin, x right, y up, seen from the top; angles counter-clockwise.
Board outline 10420.2 x 10420.2 mil, 2 copper layers (Top Layer, Bottom Layer); 286 components, 204 nets, 1058 pads, 249 vias.
Unrouted connection lines stored in the file: 1.

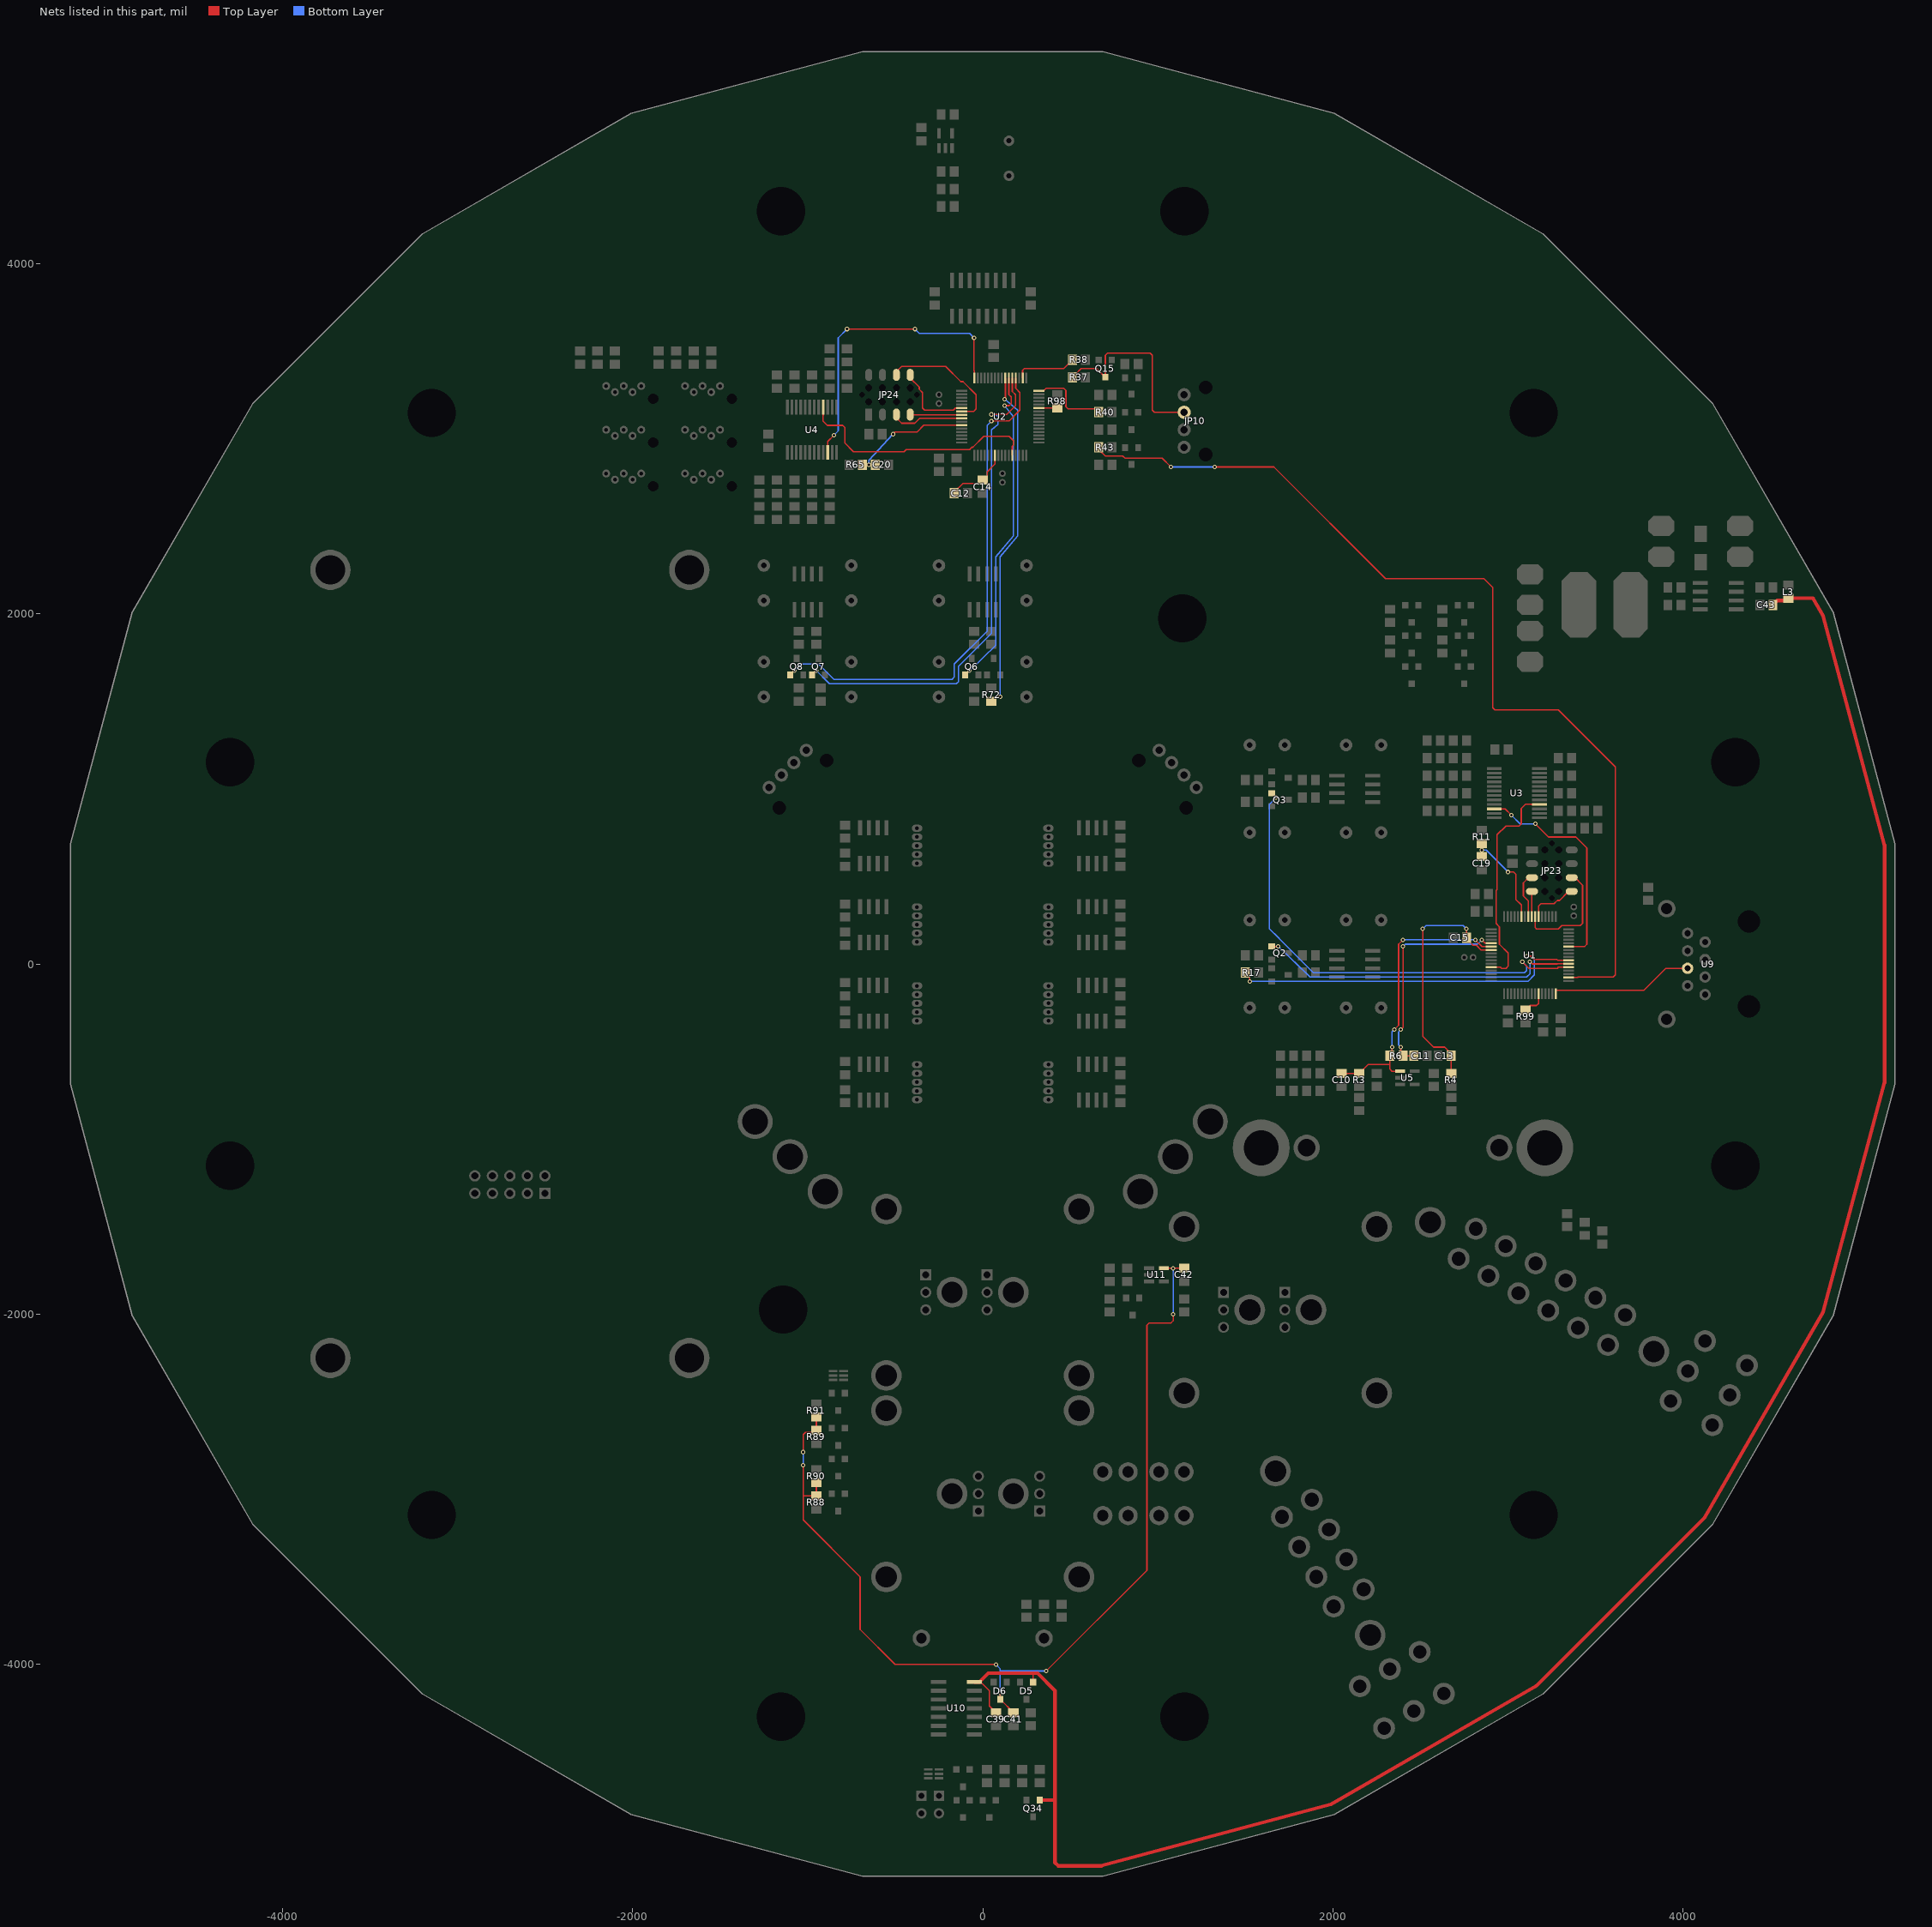
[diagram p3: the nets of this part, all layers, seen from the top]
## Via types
v1: diameter 25, hole 15, Top Layer to Bottom Layer, 204 vias
v2: diameter 40, hole 22, Top Layer to Bottom Layer, 24 vias
v3: diameter 75, hole 50, Top Layer to Bottom Layer, 21 vias

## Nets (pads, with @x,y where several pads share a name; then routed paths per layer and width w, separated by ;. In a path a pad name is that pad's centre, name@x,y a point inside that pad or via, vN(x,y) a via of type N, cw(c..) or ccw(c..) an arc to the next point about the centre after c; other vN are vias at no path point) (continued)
TB0U: Q8.1 U2.36 | length 2936.7
  Top Layer w8: Q8.1@-1100,1650 v1(-1075,1675) ; v1(50,3100) 150.5,3100 212.5,3162.5 212.5,3262.5 188.58,3286.42 U2.36@188.58,3345.47
  Bottom Layer w8: v1(-1075,1675) -1037.5,1712.5 -937.5,1712.5 -850,1625 -175,1625 -162.5,1637.5 -162.5,1712.5 25,1900 25,3075 v1(50,3100)
TB1L: Q3.1 U1.37 | length 2721
  Top Layer w8: Q3.1@1650,975 v1(1675,950) ; v1(3081.25,12.5) 3106.25,-12.5 3118.75,-25 3281.55,-25 3287.65,-18.9 U1.37@3345.47,-18.9
  Bottom Layer w8: v1(1675,950) 1637.5,912.5 1637.5,200 1687.5,150 1700,137.5 1887.5,-50 3093.75,-50 3106.25,-37.5 3106.25,-12.5 v1(3081.25,12.5)
TB1U: Q7.1 U2.37 | length 2858.4
  Top Layer w8: Q7.1@-975,1650 v1(-950,1675) ; v1(50,3137.5) 137.5,3137.5 187.5,3187.5 187.5,3250 168.9,3268.6 U2.37@168.9,3345.47
  Bottom Layer w8: v1(-950,1675) -875,1600 -150,1600 -137.5,1612.5 -137.5,1700 50,1887.5 50,3050 87.5,3081.25 87.5,3125 75,3137.5 v1(50,3137.5)
TB2L: Q2.1 U1.38 | length 1848.2
  Top Layer w8: Q2.1@1650,99.8 v1(1687.5,100) ; v1(3125,12.5) 3137.5,0 3281.25,0 3282.04,0.79 U1.38@3345.47,0.79
  Bottom Layer w8: v1(1687.5,100) 1868.75,-75 3106.25,-75 3125,-56.25 3125,-12.5 v1(3125,12.5)
TB2U: Q6.1 U2.38 | length 1859
  Top Layer w8: Q6.1@-99.8,1650 v1(-75,1675) ; v1(125,3187.5) 150,3187.5 162.5,3200 162.5,3218.75 162.5,3237.5 149.53,3250.47 ; 149.21,3250.79 149.21,3275.79 U2.38@149.21,3345.47
  Bottom Layer w8: v1(-75,1675) 75,1818.75 75,2325 175,2443.75 175,3125 v1(125,3187.5)
TB3L: R17.1 U1.39 | length 2088.8
  Top Layer w8: R17.1@1500,-50 1500,-56.25 1525,-81.25 v1(1525,-100) ; v1(3106.25,43.75) 3131.25,43.75 3143.75,31.25 3150,25 3278.44,25 3282.97,20.47 U1.39@3345.47,20.47
  Bottom Layer w8: v1(1525,-100) 3112.5,-100 3150,-62.5 3150,25 3143.75,31.25 3137.5,37.5 3131.25,43.75 v1(3106.25,43.75)
TB3U: R72.1 U2.39 | length 1948.1
  Top Layer w8: R72.1@56.25,1500 81.25,1525 v1(100,1525) ; v1(125,3225) 129.53,3229.53 U2.39@129.53,3345.47
  Bottom Layer w8: v1(100,1525) 100,2325 200,2443.75 200,3162.5 v1(125,3225)
TCKL: JP23.3 U1.57 | length 265.5
  Top Layer w8: U1.57@3115.16,270.47 3115.16,359.84 3087.5,387.5 3087.5,462.5 3118.11,493.11 JP23.3@3136.81,493.11
TCKU: JP24.3 U2.57 | length 415.5
  Top Layer w8: JP24.3@-493.11,3136.81 -493.11,3118.11 -462.5,3087.5 -387.5,3087.5 -359.84,3115.16 U2.57@-120.47,3115.16
TDIL: JP23.6 U1.55 | length 647.6
  Top Layer w8: U1.55@3154.53,270.47 3154.53,207.97 3162.5,200 3287.5,200 3306.25,218.75 3412.5,218.75 3425,231.25 3425,450 3381.89,493.11 JP23.6@3363.19,493.11
TDIU: JP24.6 U2.55 | length 724.4
  Top Layer w8: JP24.6@-493.11,3363.19 -493.11,3381.89 -462.5,3412.5 -212.5,3412.5 -125,3325 -112.5,3325 -37.5,3250 -37.5,3168.75 -51.72,3154.53 U2.55@-120.47,3154.53
TDOL: JP23.5 U1.54 | length 283.2
  Top Layer w8: U1.54@3174.21,270.47 3174.21,330.46 3187.5,343.75 3262.5,343.75 3281.25,362.5 3293.75,362.5 3343.75,412.5 JP23.5@3362.5,412.5 ; JP23.5@3362.5,413.68 JP23.5@3363.19,414.37
TDOU: JP24.5 U2.54 | length 451.3
  Top Layer w8: JP24.5@-414.37,3363.19 -412.5,3362.5 -412.5,3343.75 -362.5,3293.75 -362.5,3281.25 -343.75,3262.5 -343.75,3175 -331.25,3162.5 -167.17,3162.5 -155.46,3174.21 U2.54@-120.47,3174.21
TMSL: JP23.4 U1.56 | length 144.7
  Top Layer w8: U1.56@3134.84,270.47 3134.84,387.4 3134.84,412.4 JP23.4@3136.81,414.37
TMSU: JP24.4 U2.56 | length 291.9
  Top Layer w8: JP24.4@-412.4,3134.84 -387.4,3134.84 U2.56@-120.47,3134.84
TX0L: U1.32 U9.5 | length 823.2
  Top Layer w8: U1.32@3272.64,-170.47 3272.64,-152.36 3275,-150 3775,-150 3900,-25 U9.5@4025,-25
TX0U: R40.2 U2.32 | length 463.8
  Top Layer w8: U2.32@320.47,3272.64 347.64,3272.64 362.5,3287.5 462.5,3287.5 475,3275 475,3181.25 487.5,3168.75 650,3168.75 662.6,3156.15 R40.2@662.6,3150
TX1L: R43.2 U1.34 | length 5576.9
  Top Layer w8: R43.2@662.6,2950 662.6,2937.4 700,2900 800,2900 812.5,2887.5 1025,2887.5 v1(1075,2837.5) ; v1(1325,2837.5) 1662.5,2837.5 2300,2200 2862.5,2200 2912.5,2150 2912.5,1462.5 2925,1450 3287.5,1450 3612.5,1125 3612.5,-62.5 3600,-75 3400,-75 3397.05,-77.95 U1.34@3345.47,-77.95
  Bottom Layer w8: v1(1075,2837.5) v1(1325,2837.5)
TX1U: R38.2 U2.34 | length 354.3
  Top Layer w8: U2.34@227.95,3345.47 227.95,3390.45 237.5,3400 462.5,3400 R38.2@512.6,3450
TX3V: JP10.2 Q15.3 R37.2 | length 1130.8
  Top Layer w8: R37.2@512.6,3350 531.25,3368.75 562.5,3400 650,3400 699.21,3350.79 Q15.3@700,3350.79 700,3475 712.5,3487.5 956.25,3487.5 968.75,3475 968.75,3162.5 981.25,3150 JP10.2@1150,3150
UP/LOW_L: R99.2 U1.27 | length 144.7
  Top Layer w8: R99.2@3100,-262.5 3125,-237.5 3162.5,-237.5 3174.21,-225.79 U1.27@3174.21,-170.47
UP/LOW_U: R98.2 U2.27 | length 104.9
  Top Layer w8: U2.27@320.47,3174.21 424.21,3174.21 R98.2@425,3175
V_CURRENT_FAST: C10.2 R3.1 R6.2 U1.6@2904.53,99.21 U5.1 | length 1647.7
  Top Layer w8: C10.2@2050,-625.1 R3.1@2150,-625.1 2150,-625 2200,-575 2325.1,-575 ; v1(2337.5,-475) 2337.5,-512.6 R6.2@2325.1,-525 2325.1,-600.1 2337.6,-612.6 U5.1@2382.68,-612.6 ; v1(2350,-375) 2375,-350 2375,112.5 v1(2400,137.5) ; v1(2812.5,137.5) 2850.79,99.21 U1.6@2904.53,99.21
  Bottom Layer w8: v1(2337.5,-475) 2337.5,-387.5 v1(2350,-375) ; v1(2400,137.5) v1(2812.5,137.5)
V_CURRENT_SLOW: C11.1 R6.1 U1.5@2904.53,118.9 | length 1243.5
  Top Layer w8: v1(2387.5,-475) 2387.4,-475.1 2387.4,-525 R6.1@2399.9,-525 C11.1@2462.6,-525 ; v1(2387.5,-375) 2400,-362.5 v1(2400,100) ; v1(2850,137.5) 2868.6,118.9 U1.5@2904.53,118.9
  Bottom Layer w8: v1(2387.5,-475) 2375,-462.5 2375,-387.5 v1(2387.5,-375) ; v1(2400,100) 2412.5,112.5 2825,112.5 v1(2850,137.5)
V_GATE: C41.1 C42.2 D6.3 R88.2 R89.2 R90.2 R91.2 U11.5 | length 5783.4
  Top Layer w8: v1(-1025,-2862.5) -1025,-3175 -700,-3500 -700,-3800 -500,-4000 v1(75,-4000) ; v1(-1025,-2787.5) -1025,-2687.5 -1012.5,-2675 -962.5,-2675 -950.1,-2662.6 R89.2@-950,-2662.6 R91.2@-950,-2587.4 ; -1024.9,-3037.6 R88.2@-950,-3037.6 R90.2@-950,-2962.4 ; v1(100,-4162.5) D6.3@100,-4199.21 175,-4274.21 C41.1@175,-4275 ; v1(362.5,-4037.5) 937.5,-3462.5 937.5,-2062.5 950,-2050 1075,-2050 1087.5,-2037.5 v1(1087.5,-2000) ; U11.5@1034.65,-1737.6 1149.9,-1737.6 C42.2@1150,-1737.5
  Bottom Layer w8: v1(-1025,-2862.5) v1(-1025,-2787.5) ; v1(75,-4000) 100,-4025 v1(100,-4162.5) ; 100,-4037.5 v1(362.5,-4037.5) ; v1(1087.5,-2000) v1(1087.5,-1737.5)
V_ON: C39.2 C43.2 D5.1 L3.1 Q34.1 U10.14 | length 11998.5
  Top Layer w8: U10.14@-18.75,-4100 -12.5,-4100 37.5,-4150 37.5,-4237.5 75,-4275 C39.2@75,-4275.2 ; D5.1@287.4,-4100.79 288.29,-4100.79 288.29,-4050.79 287.5,-4050 ; L3.1@4587.5,2075 L3.1@4600,2087.5 ; L3.1@4600,2075 L3.1@4600,2087.6 ; 4741.43,2087.6 4742.05,2086.52
  Top Layer w20: U10.14@-47.64,-4100 -18.75,-4100 31.25,-4050 312.5,-4050 412.5,-4150 412.5,-5131.25 431.25,-5150 678.01,-5150 1987.83,-4799.04 3162.17,-4121.03 4121.03,-3162.17 4799.04,-1987.83 5150,-678.01 5150,678.01 4799.04,1987.83 4742.05,2086.52 ; Q34.1@325,-4775 412.5,-4775 ; C43.2@4512.4,2050 4537.5,2075 L3.1@4587.5,2075 ; L3.1@4600,2087.6 4741.43,2087.6
VCELL-L: C19.2 R11.2 U1.59 | length 581.2
  Top Layer w8: C19.2@2850,612.4 R11.2@2850,687.6 ; v1(3000,525) 3031.25,525 3043.75,512.5 3043.75,368.75 3075.79,336.71 U1.59@3075.79,270.47
  Bottom Layer w8: v1(2850,650) 2875,650 v1(3000,525)
VCELL-U: C20.2 R65.2 U2.59 | length 716.9
  Top Layer w8: R65.2@-687.7,2850 C20.2@-612.3,2850 ; v1(-512.5,3025) -500,3037.5 -375,3037.5 -336.71,3075.79 U2.59@-120.47,3075.79
  Bottom Layer w8: v1(-650,2850) -650,2875 v1(-512.5,3025)
VREF_L: C13.1 C15.2 R4.1 U1.7@2904.53,79.53 | length 1418.4
  Top Layer w8: v1(2512.5,200) 2512.5,-412.5 2575,-475 2637.5,-475 2675,-512.5 R4.1@2675,-625.1 ; v1(2762.5,200) 2762.4,199.9 C15.2@2762.4,150 2775,137.5 2781.25,125 2800,106.25 2818.75,106.25 2845.47,79.53 U1.7@2904.53,79.53
  Bottom Layer w8: v1(2512.5,200) 2531.25,218.75 2743.75,218.75 v1(2762.5,200)
VREF_U: C12.1 C14.2 U2.7 | length 375.7
  Top Layer w8: C12.1@-162.4,2687.5 -162.4,2693.85 -112.5,2743.75 -18.65,2743.75 C14.2@0,2762.4 12.4,2762.4 25,2775 25,2809.06 70.47,2854.53 U2.7@70.47,2904.53
WDIL: U1.43 U3.10 | length 1281.3
  Top Layer w8: U3.10@2921.06,885.43 2983.32,885.43 v1(3018.75,850) ; v1(3156.25,800) 3231.25,725 3387.5,725 3450,662.5 3450,112.5 3437.5,100 3346.26,100 U1.43@3345.47,99.21
  Bottom Layer w8: v1(3018.75,850) 3068.75,800 v1(3156.25,800)
WDIU: U2.48 U4.10 | length 1725.9
  Top Layer w8: U4.10@-885.43,2921.06 -885.43,2983.32 v1(-850,3018.75) ; v1(-775,3625) v1(-387.5,3625) ; v1(-50,3575) -50,3387.5 -47.64,3385.14 U2.48@-47.64,3345.47
  Bottom Layer w8: v1(-850,3018.75) -825,3043.75 -825,3575 v1(-775,3625) ; v1(-387.5,3625) -362.5,3600 -75,3600 v1(-50,3575)
XAL: U1.12 U3.16 | length 1249.9
  Top Layer w8: U1.12@2904.53,-18.9 2956.1,-18.9 2962.2,-25 2987.5,-25 3000,-12.5 3000,62.5 2950,112.5 2950,206.25 2950,212.04 2931.25,231.25 2931.25,418.75 2937.5,425 2937.5,737.5 2987.5,787.5 3062.5,787.5 3075,800 3075,887.5 3100,912.5 3131.25,912.5 3132.73,911.02 U3.16@3178.94,911.02
XAU: U2.12 U4.16 | length 1422.9
  Top Layer w8: U4.16@-911.02,3178.94 -911.02,3132.73 -912.5,3131.25 -912.5,3100 -887.5,3075 -800,3075 -787.5,3062.5 -787.5,2975 -737.5,2925 -450,2925 -437.5,2937.5 -74.54,2937.5 -62.04,2950 -56.25,2950 6.25,3012.5 150,3012.5 175,2987.5 175,2962.2 168.9,2956.1 U2.12@168.9,2904.53
pads on no net: C1.1@785,182.4 C1.1@785,632.4 C1.1@785,-267.6 C1.1@785,-717.6 C1.1@-785,267.6 C1.1@-785,717.6 C1.1@-785,-182.4 C1.1@-785,-632.4 C1.2@785,107.6 C1.2@785,557.6 C1.2@785,-342.4 C1.2@785,-792.4 C1.2@-785,342.4 C1.2@-785,792.4 C1.2@-785,-107.6 C1.2@-785,-557.6 D5.2 D6.2 Designator160.0 Designator161.0 Designator162.0 Designator163.0 Designator164.0 Designator165.0 JP1.1@375,125 JP1.1@375,575 JP1.1@375,-325 JP1.1@375,-775 JP1.1@-375,325 JP1.1@-375,775 JP1.1@-375,-125 JP1.1@-375,-575 JP1.2 JP1.3 JP1.4 JP1.5 JP9.0 JP10.0 JP11.0 JP14.0 JP15.0 JP16.0 JP17.0 JP18.0 JP19.0 JP20.0 JP21.0 JP22.0 JP23.0 JP23.8 JP24.0 JP24.8 R1.1@785,342.4 R1.1@785,792.4 R1.1@785,-107.6 R1.1@785,-557.6 R1.1@-785,107.6 R1.1@-785,557.6 R1.1@-785,-342.4 R1.1@-785,-792.4 R1.2@785,267.6 R1.2@785,717.6 R1.2@785,-182.4 R1.2@785,-632.4 R1.2@-785,182.4 R1.2@-785,632.4 R1.2@-785,-267.6 R1.2@-785,-717.6 U1.1@700,327.36 U1.1@700,777.36 U1.1@700,-122.64 U1.1@700,-572.64 U1.1@-700,122.64 U1.1@-700,572.64 U1.1@-700,-327.36 U1.1@-700,-777.36 U1.2 U1.3 U1.4 U1.5@550,122.64 U1.5@550,572.64 U1.5@550,-327.36 U1.5@550,-777.36 U1.5@-550,327.36 U1.5@-550,777.36 U1.5@-550,-122.64 U1.5@-550,-572.64 U1.6@600,122.64 U1.6@600,572.64 U1.6@600,-327.36 U1.6@600,-777.36 U1.6@-600,327.36 U1.6@-600,777.36 U1.6@-600,-122.64 U1.6@-600,-572.64 U1.7@650,122.64 U1.7@650,572.64 U1.7@650,-327.36 U1.7@650,-777.36 U1.7@-650,327.36 U1.7@-650,777.36 U1.7@-650,-122.64 U1.7@-650,-572.64 U1.8@700,122.64 U1.8@700,572.64 U1.8@700,-327.36 U1.8@700,-777.36 U1.8@-700,327.36 U1.8@-700,777.36 U1.8@-700,-122.64 U1.8@-700,-572.64 U1.16 U1.17 U1.18 U1.20 U1.21 U1.22 U1.23 U1.24 U1.25 U1.26 U1.40 U1.41 U1.42 U1.44 U1.45 U1.46 U1.47 U1.48 U1.49 U1.50 U1.51 U2.2 U2.3 U2.4 U2.5 U2.6 U2.16 U2.17 U2.18 U2.19 U2.21 U2.22 U2.23 U2.24 U2.25 U2.26 U2.28 U2.29 U2.30 U2.31 U2.40 U2.41 U2.43 U2.60 U2.61 U3.17 U3.21 U3.24 U4.17 U4.21 U4.24 U8.7 U8.9 U9.0 U9.7 U10.1 U10.2 U10.3 U10.6 U10.7 U10.8 U10.10 U10.11 U10.12 U10.13
copper on no net: | length 16772.7
  Top Layer w20: -785,-792.4 -702.4,-792.4 -700,-790 -700,-777.36 ; -785,-717.6 -775,-715 -765,-705 -735,-705 -695,-705 -665,-675 -480,-675 -430,-625 -375,-625 ; -785,-632.4 -747.6,-632.4 v2(-735,-645) ; -785,-557.6 -702.4,-557.6 -700,-560 -700,-572.64 ; -785,-342.4 -702.4,-342.4 -700,-340 -700,-327.36 ; -785,-267.6 -775,-265 -765,-255 -735,-255 -695,-255 -665,-225 -480,-225 -430,-175 -375,-175 ; -785,-182.4 -747.6,-182.4 v2(-735,-195) ; -785,-107.6 -702.4,-107.6 -700,-110 -700,-122.64 ; -785,107.6 -702.4,107.6 -700,110 -700,122.64 ; -785,182.4 -775,185 -765,195 -735,195 -695,195 -665,225 -480,225 -430,275 -375,275 ; -785,267.6 -747.6,267.6 v2(-735,255) ; -785,342.4 -702.4,342.4 -700,340 -700,327.36 ; -785,557.6 -702.4,557.6 -700,560 -700,572.64 ; -785,632.4 -775,635 -765,645 -735,645 -695,645 -665,675 -480,675 -430,725 -375,725 ; -785,717.6 -747.6,717.6 v2(-735,705) ; -785,792.4 -702.4,792.4 -700,790 -700,777.36 ; -650,-777.36 -650,-725 -635,-710 -470,-710 -435,-675 -375,-675 ; -650,-572.64 -650,-625 -635,-640 -490,-640 -450,-600 -450,-555 -430,-535 -340,-535 -325,-550 -325,-745 -355,-775 -375,-775 ; -650,-327.36 -650,-275 -635,-260 -470,-260 -435,-225 -375,-225 ; -650,-122.64 -650,-175 -635,-190 -490,-190 -450,-150 -450,-105 -430,-85 -340,-85 -325,-100 -325,-295 -355,-325 -375,-325 ; -650,122.64 -650,175 -635,190 -470,190 -435,225 -375,225 ; -650,327.36 -650,275 -635,260 -490,260 -450,300 -450,345 -430,365 -340,365 -325,350 -325,155 -355,125 -375,125 ; -650,572.64 -650,625 -635,640 -470,640 -435,675 -375,675 ; -650,777.36 -650,725 -635,710 -490,710 -450,750 -450,795 -430,815 -340,815 -325,800 -325,605 -355,575 -375,575 ; -550,-777.36 -540,-775 ; -550,-327.36 -540,-325 ; -550,122.64 -540,125 ; -550,572.64 -540,575 ; -385,-725 -375,-725 ; -385,-275 -375,-275 ; -385,175 -375,175 ; -385,625 -375,625 ; 375,-725 430,-725 480,-675 665,-675 695,-645 735,-645 765,-645 775,-635 785,-632.4 ; 375,-675 435,-675 470,-640 635,-640 650,-625 650,-572.64 ; 375,-625 385,-625 ; 375,-575 355,-575 325,-605 325,-800 340,-815 430,-815 450,-795 450,-750 490,-710 635,-710 650,-725 650,-777.36 ; 375,-275 430,-275 480,-225 665,-225 695,-195 735,-195 765,-195 775,-185 785,-182.4 ; 375,-225 435,-225 470,-190 635,-190 650,-175 650,-122.64 ; 375,-175 385,-175 ; 375,-125 355,-125 325,-155 325,-350 340,-365 430,-365 450,-345 450,-300 490,-260 635,-260 650,-275 650,-327.36 ; 375,175 430,175 480,225 665,225 695,255 735,255 765,255 775,265 785,267.6 ; 375,225 435,225 470,260 635,260 650,275 650,327.36 ; 375,275 385,275 ; 375,325 355,325 325,295 325,100 340,85 430,85 450,105 450,150 490,190 635,190 650,175 650,122.64 ; 375,625 430,625 480,675 665,675 695,705 735,705 765,705 775,715 785,717.6 ; 375,675 435,675 470,710 635,710 650,725 650,777.36 ; 375,725 385,725 ; 375,775 355,775 325,745 325,550 340,535 430,535 450,555 450,600 490,640 635,640 650,625 650,572.64 ; 540,-575 550,-572.64 ; 540,-125 550,-122.64 ; 540,325 550,327.36 ; 540,775 550,777.36 ; 700,-777.36 700,-790 702.4,-792.4 785,-792.4 ; 700,-572.64 700,-560 702.4,-557.6 785,-557.6 ; 700,-327.36 700,-340 702.4,-342.4 785,-342.4 ; 700,-122.64 700,-110 702.4,-107.6 785,-107.6 ; 700,122.64 700,110 702.4,107.6 785,107.6 ; 700,327.36 700,340 702.4,342.4 785,342.4 ; 700,572.64 700,560 702.4,557.6 785,557.6 ; 700,777.36 700,790 702.4,792.4 785,792.4 ; v2(735,-705) 747.6,-717.6 785,-717.6 ; v2(735,-255) 747.6,-267.6 785,-267.6 ; v2(735,195) 747.6,182.4 785,182.4 ; v2(735,645) 747.6,632.4 785,632.4
  Top Layer w40: -540,-775 v2(-475,-775) -425,-725 -385,-725 ; -540,-325 v2(-475,-325) -425,-275 -385,-275 ; -540,125 v2(-475,125) -425,175 -385,175 ; -540,575 v2(-475,575) -425,625 -385,625 ; 385,-625 425,-625 v2(475,-575) 540,-575 ; 385,-175 425,-175 v2(475,-125) 540,-125 ; 385,275 425,275 v2(475,325) 540,325 ; 385,725 425,725 v2(475,775) 540,775
  Bottom Layer w20: v2(-735,-557.6) v2@-722.4,-555 ; v2(-735,-107.6) v2@-722.4,-105 ; v2(-735,342.4) v2@-722.4,345 ; v2(-735,792.4) v2@-722.4,795 ; -445,-725 -322.5,-725 ; -445,-275 -322.5,-275 ; -445,175 -322.5,175 ; -445,625 -322.5,625 ; 322.5,-625 445,-625 ; 322.5,-175 445,-175 ; 322.5,275 445,275 ; 322.5,725 445,725 ; v2@722.4,-795 v2(735,-792.4) ; v2@722.4,-345 v2(735,-342.4) ; v2@722.4,105 v2(735,107.6) ; v2@722.4,555 v2(735,557.6)

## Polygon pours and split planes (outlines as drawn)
PWR- on Top Layer (hatched 45Degree grid 20 track 25, remove dead copper): 2244.61,-2687.79 2682.12,-3445.56 2249.1,-3695.56 2129.58,-3663.53 1763.08,-3028.75 1963.35,-2913.12 2244.61,-2687.79
PWR- on Top Layer (hatched 45Degree grid 20 track 25, remove dead copper): 3800.7,-2810.75 2965.43,-1975.48 1880.35,-3056.87 2249.1,-3695.56 2775.04,-3836.48
PWR+ on Top Layer (hatched 45Degree grid 20 track 25): 2501.67,-4358.03 2918.45,-4117.4 2771.57,-3863.01 2148.33,-3696.01 2126.67,-3708.51 2501.67,-4358.03
PWR+ on Top Layer (hatched 45Degree grid 20 track 25, remove dead copper): 1205.38,-3287.79 1992.88,-4651.78 2501.67,-4358.03 1714.18,-2994.04 1205.38,-3287.79
PWRISO+ on Top Layer (hatched 45Degree grid 20 track 25, remove dead copper): 1857.89,-2025 2031.36,-2200 2750,-2200 2750,-1287.5 1820.72,-1287.5 1672.04,-1437.5 1399.45,-1437.5 1237.5,-1600 1237.5,-1975 1287.5,-2025
PWR+ on Top Layer (hatched 45Degree grid 20 track 25): 1987.5,-2200 1850,-2062.5 937.5,-2062.5 937.5,-3237.5 987.5,-3287.5 1328.65,-3288.79 1988.99,-2907.54
PWRISO+ on Top Layer (hatched 45Degree grid 20 track 25): 2612.01,-2200.86 2850,-2201.15 3040.63,-1870.98 2907.94,-1375.79 2744.48,-1281.42 2313.23,-2028.37
PWR- on Top Layer (hatched 45Degree grid 20 track 25, remove dead copper): 3065.87,-1077.26 3547.59,-1355.38 3758.06,-2140.85 3445.56,-2682.12 2823.1,-2322.74 3079.35,-1878.9 2928.37,-1315.42 3003.37,-1185.51
PWRF+ on Top Layer (hatched 45Degree grid 20 track 25, remove dead copper): 487.5,-2987.5 587.5,-2887.5 587.5,-2787.5 675,-2700 825,-2700 900,-2775 900,-3237.5 637.5,-3500 -325,-3500 -400,-3425 -400,-3062.5 -325,-2987.5 437.5,-2987.5
NetQ23_1 on Top Layer (hatched 45Degree grid 20 track 25, remove dead copper): 500,-2414.29 500,-2450 -550,-2450 -550,-2342.86 -550,-2025 -475,-1950 325,-1950 500,-2125
NetQ23_1 on Top Layer (hatched 45Degree grid 20 track 25, remove dead copper): -500,-2485.71 -500,-2450 550,-2450 550,-2557.14 550,-2875 475,-2950 -325,-2950 -500,-2775
PWR- on Top Layer (hatched 90Degree grid 5 track 10): -5053.75,-195 -4513.75,-195 -4513.75,185 -5053.75,185
BAT+ on Top Layer (hatched 45Degree grid 20 track 25, remove dead copper): -1200,-650 -1400,-650 -1550.5,-802.01 -1550.5,-1299.5 -937.5,-1912.5 -550,-1912.5 -550,-2050 425,-2050 500,-1975 500,-1231.25 -575,-1230.75 -1150,-650
NetQ12_7 on Top Layer (hatched 45Degree grid 20 track 25, remove dead copper): -1025,2237.5 -1262.5,2237.5 -1287.5,2262.5 -1287.5,2287.5 -1262.5,2312.5 -1025,2312.5
NetQ11_7 on Top Layer (hatched 45Degree grid 20 track 25, remove dead copper): -25,2237.5 -262.5,2237.5 -287.5,2262.5 -287.5,2287.5 -262.5,2312.5 -25,2312.5
NetQ10_7 on Top Layer (hatched 45Degree grid 20 track 25, remove dead copper): 2237.5,1025 2237.5,1262.5 2262.5,1287.5 2287.5,1287.5 2312.5,1262.5 2312.5,1025
NetQ9_7 on Top Layer (hatched 45Degree grid 20 track 25, remove dead copper): 2237.5,25 2237.5,262.5 2262.5,287.5 2287.5,287.5 2312.5,262.5 2312.5,25
NetQ12_5 on Top Layer (hatched 45Degree grid 20 track 25, remove dead copper): -975,2312.5 -737.5,2312.5 -712.5,2287.5 -712.5,2262.5 -737.5,2237.5 -975,2237.5
NetQ11_5 on Top Layer (hatched 45Degree grid 20 track 25, remove dead copper): 25,2312.5 262.5,2312.5 287.5,2287.5 287.5,2262.5 262.5,2237.5 25,2237.5
NetQ10_5 on Top Layer (hatched 45Degree grid 20 track 25, remove dead copper): 2312.5,975 2312.5,737.5 2287.5,712.5 2262.5,712.5 2237.5,737.5 2237.5,975
NetQ9_5 on Top Layer (hatched 45Degree grid 20 track 25, remove dead copper): 2312.5,-25 2312.5,-262.5 2287.5,-287.5 2262.5,-287.5 2237.5,-262.5 2237.5,-25
PWR- on Top Layer (hatched 45Degree grid 20 track 25, remove dead copper): 2800,-525 2850,-475 3600,-475 3650,-525 3650,-1887.5 3237.5,-1887.5 3237.5,-1506.74 3225,-1494.46 2900,-1310.22 2900,-1113.7 2800,-1015.43
BAT- on Top Layer (hatched 45Degree grid 20 track 25, remove dead copper): 650,-1300 900,-1550 1000,-1550 1150,-1400 1650,-1400 1800,-1250 1800,-887.5 1750,-837.5 1587.5,-837.5 1498.41,-748.41 1498.41,-450 1600,-350 1600,-225 1550.2,-175 1200.2,-175 1200.2,-650 1200,-650 650,-1200
no net on Bottom Layer (hatched 90Degree grid 20 track 25): -845,315 -845,400 -275,400 -275,315
no net on Bottom Layer (hatched 90Degree grid 20 track 25, remove dead copper): -845,50 -275,50 -275,290 -845,290
no net on Bottom Layer (hatched 90Degree grid 20 track 25): -845,-135 -845,-50 -275,-50 -275,-135
no net on Bottom Layer (hatched 90Degree grid 20 track 25, remove dead copper): -845,-400 -275,-400 -275,-160 -845,-160
no net on Bottom Layer (hatched 90Degree grid 20 track 25): -845,-585 -845,-500 -275,-500 -275,-585
no net on Bottom Layer (hatched 90Degree grid 20 track 25, remove dead copper): -845,-850 -275,-850 -275,-610 -845,-610
no net on Bottom Layer (hatched 90Degree grid 20 track 25): -845,765 -845,850 -275,850 -275,765
no net on Bottom Layer (hatched 90Degree grid 20 track 25, remove dead copper): -845,500 -275,500 -275,740 -845,740
no net on Bottom Layer (hatched 90Degree grid 20 track 25): 845,585 845,500 275,500 275,585
no net on Bottom Layer (hatched 90Degree grid 20 track 25, remove dead copper): 845,850 275,850 275,610 845,610
no net on Bottom Layer (hatched 90Degree grid 20 track 25): 845,135 845,50 275,50 275,135
no net on Bottom Layer (hatched 90Degree grid 20 track 25, remove dead copper): 845,400 275,400 275,160 845,160
no net on Bottom Layer (hatched 90Degree grid 20 track 25): 845,-315 845,-400 275,-400 275,-315
no net on Bottom Layer (hatched 90Degree grid 20 track 25, remove dead copper): 845,-50 275,-50 275,-290 845,-290
no net on Bottom Layer (hatched 90Degree grid 20 track 25): 845,-765 845,-850 275,-850 275,-765
no net on Bottom Layer (hatched 90Degree grid 20 track 25, remove dead copper): 845,-500 275,-500 275,-740 845,-740
PWR+ on Bottom Layer (hatched 45Degree grid 20 track 25): 1987.5,-2200 1850,-2062.5 937.5,-2062.5 937.5,-3237.5 987.5,-3287.5 1328.65,-3288.79 1988.99,-2907.54
BAT- on Bottom Layer (hatched 45Degree grid 20 track 25, remove dead copper): 650,-1300 900,-1550 1000,-1550 1150,-1400 1650,-1400 1800,-1250 1800,-887.5 1750,-837.5 1587.5,-837.5 1498.41,-748.41 1498.41,-450 1600,-350 1600,-225 1550.2,-175 1200.2,-175 1200.2,-650 1200,-650 650,-1200
PWR- on Bottom Layer (hatched 45Degree grid 20 track 25, remove dead copper): 2244.61,-2687.79 2978.37,-3958.68 2469.58,-4252.43 1785.83,-3068.14 1986.09,-2952.51 2244.61,-2687.79
PWR- on Bottom Layer (hatched 45Degree grid 20 track 25, remove dead copper): 3800.7,-2810.75 2965.43,-1975.48 1879.37,-3059.16 2174.87,-3570.99 2810.75,-3800.7
PWR+ on Bottom Layer (hatched 45Degree grid 20 track 25, remove dead copper): 1205.38,-3287.79 1605.38,-3980.61 2114.17,-3686.86 1714.17,-2994.04 1205.38,-3287.79
PWR- on Bottom Layer (hatched 45Degree grid 20 track 25, remove dead copper): 2800,-450 2850,-450 4300,-450 4300,-500 4300,-1887.5 4074.51,-2280.25 3230.13,-1792.75 3379.05,-1532.32 2976.47,-1300 2976.47,-1100 2800,-1000
PWR- on Bottom Layer (hatched 45Degree grid 20 track 25, remove dead copper): 3065.87,-1077.26 3547.59,-1355.38 3758.06,-2140.85 3445.56,-2682.12 2823.1,-2322.74 3079.35,-1878.9 2928.37,-1315.42 3003.37,-1185.51
PWRISO+ on Bottom Layer (hatched 45Degree grid 20 track 25): 2612.01,-2200.86 2850,-2201.15 3040.63,-1870.98 2907.94,-1375.79 2744.48,-1281.42 2313.23,-2028.37
PWR- on Bottom Layer (hatched 45Degree grid 20 track 25, remove dead copper): 4381.68,2760.71 3634.73,2329.46 4084.73,1550.03 4831.68,1981.28
PWR- on Bottom Layer (hatched 45Degree grid 20 track 25, remove dead copper): 2800,-450 2500,-450 2450,-450 2450,-650 2500,-700 2800,-700 2800,-452.69
PWR- on Bottom Layer (hatched 45Degree grid 20 track 25, remove dead copper): 5175,700 4312.5,700 4312.5,-700 5175,-700
PWR- on Bottom Layer (hatched 45Degree grid 20 track 25): 4817.49,2015.54 3984.38,1792.31 4346.73,440.01 5179.84,663.24
PWR- on Bottom Layer (hatched 45Degree grid 20 track 25): 5179.84,-663.24 4346.73,-440.01 3984.38,-1792.31 4817.49,-2015.54
PWR- on Bottom Layer (hatched 45Degree grid 20 track 25, remove dead copper): 2450,-450 2450,2450 2762.5,2762.5 4375,2762.5 4375,-450 2637.5,-450
NetQ23_1 on Bottom Layer (hatched 45Degree grid 20 track 25, remove dead copper): 500,-2414.29 500,-2450 -550,-2450 -550,-2342.86 -550,-2025 -475,-1950 325,-1950 500,-2125
BAT+ on Bottom Layer (hatched 45Degree grid 20 track 25, remove dead copper): -1200,-650 -1400,-650 -1550,-800 -1550,-1300 -937.5,-1912.5 225,-1912.5 300,-1836.75 300,-1230.75 -575,-1230.75 -1150,-650
PWRISO+ on Bottom Layer (hatched 45Degree grid 20 track 25, remove dead copper): 1857.89,-2025 2031.36,-2200 2750,-2200 2750,-1287.5 1820.72,-1287.5 1672.04,-1437.5 1399.45,-1437.5 1237.5,-1600 1237.5,-1975 1287.5,-2025
PWR- on Bottom Layer (hatched 45Degree grid 20 track 25, remove dead copper): 3057.78,-3079.69 2668.87,-3468.6 2315.32,-3115.04 2704.23,-2726.14
NetQ23_1 on Bottom Layer (hatched 45Degree grid 20 track 25, remove dead copper): -500,-2485.71 -500,-2450 550,-2450 550,-2557.14 550,-2875 475,-2950 -325,-2950 -500,-2775
PWRF+ on Bottom Layer (hatched 45Degree grid 20 track 25, remove dead copper): 487.5,-2987.5 587.5,-2887.5 587.5,-2787.5 675,-2700 825,-2700 900,-2775 900,-3237.5 637.5,-3500 -325,-3500 -400,-3425 -400,-3062.5 -325,-2987.5 437.5,-2987.5
PWR- on Bottom Layer (hatched 45Degree grid 20 track 25): -663.24,-5179.84 -440.01,-4346.73 -1792.31,-3984.38 -2015.54,-4817.49
PWR- on Bottom Layer (hatched 45Degree grid 20 track 25, remove dead copper): 700,-5175 700,-4312.5 -700,-4312.5 -700,-5175
PWR- on Bottom Layer (hatched 45Degree grid 20 track 25, remove dead copper): 2015.54,-4817.49 1792.31,-3984.38 440.01,-4346.73 663.24,-5179.84
PWR- on Bottom Layer (hatched 45Degree grid 20 track 25, remove dead copper): 3193.72,-4131.68 2762.47,-3384.73 1550.03,-4084.73 1981.28,-4831.68
PWR- on Bottom Layer (hatched 45Degree grid 20 track 25): 4154.25,-3164.3 3544.37,-2554.42 2554.42,-3544.37 3164.3,-4154.25
PWR- on Bottom Layer (hatched 45Degree grid 20 track 25, remove dead copper): 4831.68,-1981.28 4084.73,-1550.03 3384.73,-2762.47 4131.68,-3193.72
AGNDU on Bottom Layer (hatched 45Degree grid 20 track 25, remove dead copper): -2350,3525 -2350,2625 -2325,2600 -1424.24,2601.76 -1399.24,2576.76 -1399.24,1426.76 -1374.24,1401.76 375.76,1401.76 400.76,1426.76 400.76,4876.36 375.76,4901.76 -400,4900 -425,4875 -425,4225 -900,3750 -2125,3750
PWR- on Bottom Layer (hatched 45Degree grid 20 track 25): -2475,-1275 -2437.5,-1237.5 -2437.5,-1187.5 -2475,-1150 -2925,-1150 -3000,-1225 -3000,-4250 -2923.08,-4287.93 -2493.75,-3543.75 -2493.75,-1293.75 -2475,-1275
PWR- on Bottom Layer (hatched 45Degree grid 20 track 25): -1981.28,-4831.68 -1550.03,-4084.73 -2491.83,-3540.98 -2923.08,-4287.93

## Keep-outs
Keep-Out Layer:
  circle w50: c0,0 r1335
  circle w12.5: c1139.39,1973.48 r168.75
  circle w12.5: c-1139.39,-1973.48 r168.75
  circle w25: c4298.37,1151.74 r175
  circle w25: c3146.63,3146.63 r175
  circle w25: c1151.74,4298.37 r175
  circle w25: c-1151.74,4298.37 r175
  circle w25: c-3146.63,3146.63 r175
  circle w25: c-4298.37,1151.74 r175
  circle w25: c-4298.37,-1151.74 r175
  circle w25: c-3146.63,-3146.63 r175
  circle w25: c-1151.74,-4298.37 r175
  circle w25: c1151.74,-4298.37 r175
  circle w25: c3146.63,-3146.63 r175
  circle w25: c4298.37,-1151.74 r175

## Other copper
Top Layer:
  rectangle: -860,40 -825,410
  rectangle: -835,385 -265,410
  rectangle: -835,40 -265,65
  rectangle: -625,40 -575,165
  rectangle: -625,285 -500,405
  rectangle: -860,-410 -825,-40
  rectangle: -835,-65 -265,-40
  rectangle: -835,-410 -265,-385
  rectangle: -625,-410 -575,-285
  rectangle: -625,-165 -500,-45
  rectangle: -860,-860 -825,-490
  rectangle: -835,-515 -265,-490
  rectangle: -835,-860 -265,-835
  rectangle: -625,-860 -575,-735
  rectangle: -625,-615 -500,-495
  rectangle: -860,490 -825,860
  rectangle: -835,835 -265,860
  rectangle: -835,490 -265,515
  rectangle: -625,490 -575,615
  rectangle: -625,735 -500,855
  region: 860,860 825,860 825,490 860,490
  region: 835,515 265,515 265,490 835,490
  region: 835,860 265,860 265,835 835,835
  region: 625,860 575,860 575,735 625,735
  region: 625,615 500,615 500,495 625,495
  region: 860,410 825,410 825,40 860,40
  region: 835,65 265,65 265,40 835,40
  region: 835,410 265,410 265,385 835,385
  region: 625,410 575,410 575,285 625,285
  region: 625,165 500,165 500,45 625,45
  region: 860,-40 825,-40 825,-410 860,-410
  region: 835,-385 265,-385 265,-410 835,-410
  region: 835,-40 265,-40 265,-65 835,-65
  region: 625,-40 575,-40 575,-165 625,-165
  region: 625,-285 500,-285 500,-405 625,-405
  region: 860,-490 825,-490 825,-860 860,-860
  region: 835,-835 265,-835 265,-860 835,-860
  region: 835,-490 265,-490 265,-515 835,-515
  region: 625,-490 575,-490 575,-615 625,-615
  region: 625,-735 500,-735 500,-855 625,-855
  text "Copyright" at 115,820 h35 r270
  text "2005" at 45,740 h35 r270
  text "E" at 205,725 h80 r270
  text "P" at -165,675 h80 r90
  text "P" at 165,675 h80 r270
  text "E" at -205,625 h80 r90
  text "2005" at -45,610 h35 r90
  text "Copyright" at -115,530 h35 r90
  text "Copyright" at 115,370 h35 r270
  text "2005" at 45,290 h35 r270
  text "E" at 205,275 h80 r270
  text "P" at -165,225 h80 r90
  text "P" at 165,225 h80 r270
  text "E" at -205,175 h80 r90
  text "2005" at -45,160 h35 r90
  text "Copyright" at -115,80 h35 r90
  text "27P8S Li-Ion" at -4393.75,25 h40
  text "E" at -4893.75,-25 h150
  text "P" at -4783.75,-75 h150
  text "PCB-150 - Rev1.0" at -4463.75,-75 h40
  text "Copyright" at 115,-80 h35 r270
  text "2005" at 45,-160 h35 r270
  text "Technologies" at -5013.75,-165 h40
  text "E" at 205,-175 h80 r270
  text "P" at -165,-225 h80 r90
  text "P" at 165,-225 h80 r270
  text "E" at -205,-275 h80 r90
  text "2005" at -45,-290 h35 r90
  text "Copyright" at -115,-370 h35 r90
  text "Copyright" at 115,-530 h35 r270
  text "2005" at 45,-610 h35 r270
  text "E" at 205,-625 h80 r270
  text "P" at -165,-675 h80 r90
  text "P" at 165,-675 h80 r270
  text "E" at -205,-725 h80 r90
  text "2005" at -45,-740 h35 r90
  text "Copyright" at -115,-820 h35 r90
Bottom Layer:
  text "TempSens" at -60,825 h40 r90
  text "PCB-151" at -190,800 h40 r90
  text "Rev1.0" at -125,780 h40 r90
  text "Rev1.0" at 125,570 h40 r270
  text "PCB-151" at 190,550 h40 r270
  text "TempSens" at 60,525 h40 r270
  text "TempSens" at -60,375 h40 r90
  text "PCB-151" at -190,350 h40 r90
  text "Rev1.0" at -125,330 h40 r90
  text "Rev1.0" at 125,120 h40 r270
  text "PCB-151" at 190,100 h40 r270
  text "TempSens" at 60,75 h40 r270
  text "Copyright 2005" at -4037.5,12.5 h60
  text "TempSens" at -60,-75 h40 r90
  text "Eagle Picher" at -4100,-87.5 h60
  text "PCB-151" at -190,-100 h40 r90
  text "Rev1.0" at -125,-120 h40 r90
  text "Rev1.0" at 125,-330 h40 r270
  text "PCB-151" at 190,-350 h40 r270
  text "TempSens" at 60,-375 h40 r270
  text "TempSens" at -60,-525 h40 r90
  text "PCB-151" at -190,-550 h40 r90
  text "Rev1.0" at -125,-570 h40 r90
  text "Rev1.0" at 125,-780 h40 r270
  text "PCB-151" at 190,-800 h40 r270
  text "TempSens" at 60,-825 h40 r270
Multi-Layer:
  lines w10 net +3DU: -1500,3300 -1487.63,3312.37

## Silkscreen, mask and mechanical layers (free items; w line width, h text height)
Top Overlay:
  drawing of 192 lines, arcs and shapes, not listed
  text "Observe" at 50,4620 h30
  text "Polarity" at 50,4560 h30
  text "Upper" at -612.5,3425 h40
  text "Firmware" at -675,3362.5 h40
  text "Temp3" at -2137.5,3150 h40
  text "Temp0" at -1687.5,3150 h40
  text "Auxiliary" at 1400,3125 h60
  text "Serial" at 1487.5,3025 h60
  text "Temp4" at -2137.5,2900 h40
  text "Temp1" at -1687.5,2900 h40
  text "Temp5" at -2137.5,2650 h40
  text "Temp2" at -1687.5,2650 h40
  text "Sense" at 787.5,1487.5 h60
  text "Layer 1-4" at 700,1400 h60
  text "5" at -1129.5,1333 h40
  text "4" at 1125.37,1312.13 h40
  text "6" at -1200.21,1262.29 h40
  text "3" at 1196.08,1241.42 h40
  text "7" at -1270.92,1191.58 h40
  text "2" at 1266.79,1170.71 h40
  text "8" at -1341.63,1120.87 h40
  text "1" at 1337.5,1100 h40
  text "Sense" at -1612.5,825 h60
  text "Layer 5-8" at -1700,737.5 h60
  text "Lower" at 3425,550 h40
  text "Firmware" at 3362.5,487.5 h40
  text "27P8S Li-Ion" at -4393.75,25 h40
  text "PCB-150 - Rev1.0" at -4463.75,-75 h40
  text "Technologies" at -5013.75,-165 h40
  text "Ethernet" at 5000,-212.5 h60 r90
  text "Comms" at -2850,-1150 h60
  text "BATT-" at 1062.5,-1337.5 h80
  text "BATT+" at -1425,-1350 h80
  text "TAPE" at -375,-1487.5 h40
  text "TAPE" at 225,-1487.5 h40
  text "TAPE" at 1325,-1587.5 h40
  text "TAPE" at 1925,-1587.5 h40
  text "PWR-" at 4313.72,-2171.58 h60 r60
  text "TAPE" at -225,-2262.5 h40 r180
  text "TAPE" at 375,-2262.5 h40 r180
  text "TAPE" at 1475,-2362.5 h40 r180
  text "TAPE" at 2075,-2362.5 h40 r180
  text "TAPE" at -375,-2637.5 h40
  text "TAPE" at 225,-2637.5 h40
  text "Bus" at 4412.5,-2662.5 h60 r60
  text "Discharge" at 4262.5,-2762.5 h60 r60
  text "MINI 25A" at 762.5,-2800 h40
  text "Replace BOTH fuses" at 587.5,-3037.5 h40
  text "Use SAME rating" at 637.5,-3287.5 h40
  text "TAPE" at -225,-3412.5 h40 r180
  text "TAPE" at 375,-3412.5 h40 r180
  text "PWR+" at 2650,-4037.5 h60 r30
  text "Charge Bus" at 2312.5,-4587.5 h60 r30
  text "Local" at -512.5,-4987.5 h40
  text "Firmware" at -250,-4987.5 h40
  text "Enables" at -425,-5050 h40
Board Outline:
  circle w10: c0,0 r1350
  lines w8: -5205.08,-685.26 -4850.37,-2009.09 -4165.1,-3196 -3196,-4165.1 -2009.09,-4850.37 -685.26,-5205.08 685.26,-5205.08 2009.09,-4850.37 3196,-4165.1 4165.1,-3196 4850.37,-2009.09 5205.08,-685.26 5205.09,685.26 4850.37,2009.09 4165.1,3196 3196,4165.1 2009.09,4850.37 685.26,5205.08 -685.26,5205.09 -2009.09,4850.37 -3196,4165.1 -4165.1,3196 -4850.37,2009.09 -5205.08,685.26 -5205.08,-685.26
  lines w10: -875,-875 -875,-475 -225,-475 ccw(c-175,-475) -125,-475 -25,-475 -25,-875 -125,-875 ccw(c-175,-875) -225,-875 -875,-875 ; -875,-425 -875,-25 -225,-25 ccw(c-175,-25) -125,-25 -25,-25 -25,-425 -125,-425 ccw(c-175,-425) -225,-425 -875,-425 ; -875,25 -875,425 -225,425 ccw(c-175,425) -125,425 -25,425 -25,25 -125,25 ccw(c-175,25) -225,25 -875,25 ; -875,475 -875,875 -225,875 ccw(c-175,875) -125,875 -25,875 -25,475 -125,475 ccw(c-175,475) -225,475 -875,475 ; 25,-875 125,-875 cw(c175,-875) 225,-875 875,-875 875,-475 225,-475 cw(c175,-475) 125,-475 25,-475 25,-875 ; 25,-425 125,-425 cw(c175,-425) 225,-425 875,-425 875,-25 225,-25 cw(c175,-25) 125,-25 25,-25 25,-425 ; 25,25 125,25 cw(c175,25) 225,25 875,25 875,425 225,425 cw(c175,425) 125,425 25,425 25,25 ; 25,475 125,475 cw(c175,475) 225,475 875,475 875,875 225,875 cw(c175,875) 125,875 25,875 25,475
Mech Reference:
  lines w10: 4825,-225 5250,-225 5250,225 4825,225
  text "1.07 (8)" at -700,2437.5 h60
  text "1.07 (8)" at 1812.5,475 h60
  text "RJ45 plug" at 5325,-262.5 h60 r90
  text "Ht=0.37in" at 5425,-262.5 h60 r90
  text "0.855" at 2275,-1143.75 h60
  text "0.95" at 1687.5,-1487.5 h60
  text "1.10" at 4182.92,-2045.02 h60 r330
  text "0.95" at -112.5,-2425 h60
  text "0.95" at -112.5,-2537.5 h60
  text "1.10" at 2600,-3862.5 h60 r300
Mechanical Cells:
  circle w10: c5382.82,-708.66 r708.66
  circle w10: c5382.82,708.66 r708.66
  circle w10: c4155.4,0 r708.66
  circle w10: c2985.39,799.93 r708.66
  circle w10: c1572.16,907.69 r708.66
  circle w10: c1572.16,-907.69 r708.66
  circle w10: c2985.39,-799.93 r708.66
  circle w10: c2185.45,-2185.45 r708.66
  circle w10: c3598.68,-2077.7 r708.66
  circle w10: c5015.99,-2077.69 r708.66
  circle w10: c4307.33,-3305.13 r708.66
  circle w10: c2077.7,-3598.68 r708.66
  circle w10: c799.93,-2985.39 r708.66
  circle w10: c0,-1815.38 r708.66
  circle w10: c2077.69,-5015.99 r708.66
  circle w10: c3305.13,-4307.33 r708.66
  circle w10: c708.66,-5382.82 r708.66
  circle w10: c-799.93,-2985.39 r708.66
  circle w10: c-708.66,-5382.82 r708.66
  circle w10: c-2077.69,-5015.99 r708.66
  circle w10: c-2077.7,-3598.68 r708.66
  circle w10: c-2185.45,-2185.45 r708.66
  circle w10: c-1572.16,-907.69 r708.66
  circle w10: c-3305.13,-4307.33 r708.66
  circle w10: c-4307.33,-3305.13 r708.66
  circle w10: c-3598.68,-2077.7 r708.66
  circle w10: c-5015.99,-2077.69 r708.66
  circle w10: c-2985.39,-799.93 r708.66
  circle w10: c-4155.4,0 r708.66
  circle w10: c-5382.82,-708.66 r708.66
  circle w10: c-5382.82,708.66 r708.66
  circle w10: c-2985.39,799.68 r708.66
  circle w10: c-1572.16,907.69 r708.66
  circle w10: c-2185.45,2185.45 r708.66
  circle w10: c-3598.68,2077.7 r708.66
  circle w10: c-5015.99,2077.69 r708.66
  circle w10: c-4307.33,3305.13 r708.66
  circle w10: c-2077.7,3598.68 r708.66
  circle w10: c-799.93,2985.39 r708.66
  circle w10: c0,1815.38 r708.66
  circle w10: c799.93,2985.39 r708.66
  circle w10: c2185.45,2185.45 r708.66
  circle w10: c3598.68,2077.7 r708.66
  circle w10: c5015.99,2077.69 r708.66
  circle w10: c4307.33,3305.13 r708.66
  circle w10: c2077.7,3598.68 r708.66
  circle w10: c3305.13,4307.33 r708.66
  circle w10: c2077.69,5015.99 r708.66
  circle w10: c0,4155.4 r708.66
  circle w10: c708.66,5382.82 r708.66
  circle w10: c-708.66,5382.82 r708.66
  circle w10: c-2077.69,5015.99 r708.66
  circle w10: c-3305.13,4307.33 r708.66
  circle w10: c0,-4155.4 r708.66
  lines w8: -5949,-783 -5949,783 ; -5948.95,-783.39 -5543.64,-2296.03 ; -5948.95,783.39 -5543.64,2296.03 ; -5543.49,-2296.4 -4760.49,-3652.6 ; -5543.49,2296.4 -4760.49,3652.6 ; -4760.24,-3652.91 -3652.91,-4760.24 ; -4760.24,3652.91 -3652.91,4760.24 ; -3652.6,-4760.49 -2296.4,-5543.49 ; -3652.6,4760.49 -2296.4,5543.49 ; -2296.03,-5543.64 -783.39,-5948.95 ; -2296.03,5543.64 -783.39,5948.95 ; -1039.64,831.42 -707.11,565.69 ; -783,-5949 783,-5949 ; -783,5949 783,5949 ; -133.79,866.23 133.79,866.23 ; 329.53,843.45 399.07,1020.98 ; 783.39,-5948.95 2296.03,-5543.64 ; 783.39,5948.95 2296.03,5543.64 ; 2296.4,-5543.49 3652.6,-4760.49 ; 2296.4,5543.49 3652.6,4760.49 ; 3652.91,-4760.24 4760.24,-3652.91 ; 3652.91,4760.24 4760.24,3652.91 ; 4760.49,-3652.6 5543.49,-2296.4 ; 4760.49,3652.6 5543.49,2296.4 ; 5543.64,-2296.03 5948.95,-783.39 ; 5543.64,2296.03 5948.95,783.39 ; 5949,-783 5949,783 ; -1300,-225 -1150,-300 -1150,300 -1300,225 -1300,-225 ; 1150,-300 1150,300 1300,225 1300,-225 1150,-300
  lines w10: -1039.64,831.42 ccw(c0,0) -1240.84,482.09 cw(c-1815.38,0) -1240.84,-482.09 ccw(c0,0) -1037.92,-833.56 cw(c-907.69,-1572.16) -202.92,-1315.65 ccw(c0,0) 202.92,-1315.65 cw(c907.69,-1572.16) 1037.92,-833.56 ccw(c0,0) 1240.84,-482.09 cw(c1815.38,0) 1240.84,482.09 ccw(c0,0) 1037.92,833.56 cw(c907.69,1572.16) 399.07,1020.98 ; -707.11,565.69 ccw(c-636.4,636.4) -565.69,565.69 cw(c0,0) 207.06,772.74 ccw(c232.94,869.33) 329.53,843.45 ; -650.86,1182.74 cw(c-530.33,963.72) -282.47,996.35 ; -282.51,996.65 ccw(c-133.79,1016.23) -114.21,867.51 ; 114.21,867.51 ccw(c133.79,1016.23) 282.51,996.65 ; 282.47,996.35 cw(c530.33,963.72) 650.86,1182.74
